# Generated deterministically by seda-macro-lef-normalizer-v1; recipe orfs-asap7-fakeram-m4-v1.
VERSION 5.8 ;
BUSBITCHARS "[]" ;
DIVIDERCHAR "/" ;

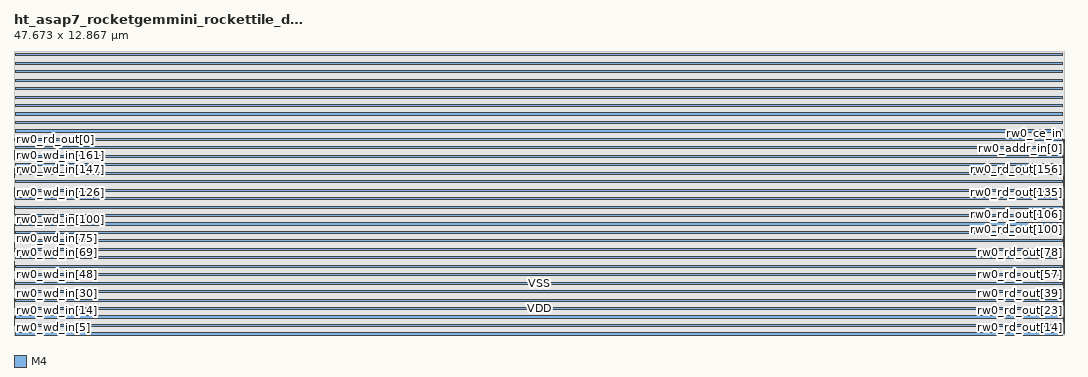
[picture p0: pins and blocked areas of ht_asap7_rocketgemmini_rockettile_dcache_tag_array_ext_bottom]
MACRO ht_asap7_rocketgemmini_rockettile_dcache_tag_array_ext_bottom
  FOREIGN ht_asap7_rocketgemmini_rockettile_dcache_tag_array_ext_bottom 0 0 ;
  CLASS BLOCK ;
  ORIGIN 0 0 ;
  SIZE 47.673 BY 12.867 ;
  SYMMETRY X Y R90 ;
  PIN rw0_wmask_in[0]
    DIRECTION INPUT ;
    USE SIGNAL ;
    SHAPE ABUTMENT ;
    PORT
      LAYER M4 ;
      RECT 0 0.048 0.024 0.072 ;
    END
  END rw0_wmask_in[0]
  PIN rw0_wmask_in[1]
    DIRECTION INPUT ;
    USE SIGNAL ;
    SHAPE ABUTMENT ;
    PORT
      LAYER M4 ;
      RECT 0 0.096 0.024 0.12 ;
    END
  END rw0_wmask_in[1]
  PIN rw0_wmask_in[2]
    DIRECTION INPUT ;
    USE SIGNAL ;
    SHAPE ABUTMENT ;
    PORT
      LAYER M4 ;
      RECT 0 0.144 0.024 0.168 ;
    END
  END rw0_wmask_in[2]
  PIN rw0_wmask_in[3]
    DIRECTION INPUT ;
    USE SIGNAL ;
    SHAPE ABUTMENT ;
    PORT
      LAYER M4 ;
      RECT 0 0.192 0.024 0.216 ;
    END
  END rw0_wmask_in[3]
  PIN rw0_wmask_in[4]
    DIRECTION INPUT ;
    USE SIGNAL ;
    SHAPE ABUTMENT ;
    PORT
      LAYER M4 ;
      RECT 0 0.24 0.024 0.264 ;
    END
  END rw0_wmask_in[4]
  PIN rw0_wmask_in[5]
    DIRECTION INPUT ;
    USE SIGNAL ;
    SHAPE ABUTMENT ;
    PORT
      LAYER M4 ;
      RECT 0 0.288 0.024 0.312 ;
    END
  END rw0_wmask_in[5]
  PIN rw0_wmask_in[6]
    DIRECTION INPUT ;
    USE SIGNAL ;
    SHAPE ABUTMENT ;
    PORT
      LAYER M4 ;
      RECT 0 0.336 0.024 0.36 ;
    END
  END rw0_wmask_in[6]
  PIN rw0_wmask_in[7]
    DIRECTION INPUT ;
    USE SIGNAL ;
    SHAPE ABUTMENT ;
    PORT
      LAYER M4 ;
      RECT 0 0.384 0.024 0.408 ;
    END
  END rw0_wmask_in[7]
  PIN rw0_wd_in[0]
    DIRECTION INPUT ;
    USE SIGNAL ;
    SHAPE ABUTMENT ;
    PORT
      LAYER M4 ;
      RECT 0 0.432 0.024 0.456 ;
    END
  END rw0_wd_in[0]
  PIN rw0_wd_in[1]
    DIRECTION INPUT ;
    USE SIGNAL ;
    SHAPE ABUTMENT ;
    PORT
      LAYER M4 ;
      RECT 0 0.48 0.024 0.504 ;
    END
  END rw0_wd_in[1]
  PIN rw0_wd_in[2]
    DIRECTION INPUT ;
    USE SIGNAL ;
    SHAPE ABUTMENT ;
    PORT
      LAYER M4 ;
      RECT 0 0.528 0.024 0.552 ;
    END
  END rw0_wd_in[2]
  PIN rw0_wd_in[3]
    DIRECTION INPUT ;
    USE SIGNAL ;
    SHAPE ABUTMENT ;
    PORT
      LAYER M4 ;
      RECT 0 0.576 0.024 0.6 ;
    END
  END rw0_wd_in[3]
  PIN rw0_wd_in[4]
    DIRECTION INPUT ;
    USE SIGNAL ;
    SHAPE ABUTMENT ;
    PORT
      LAYER M4 ;
      RECT 0 0.624 0.024 0.648 ;
    END
  END rw0_wd_in[4]
  PIN rw0_wd_in[5]
    DIRECTION INPUT ;
    USE SIGNAL ;
    SHAPE ABUTMENT ;
    PORT
      LAYER M4 ;
      RECT 0 0.672 0.024 0.696 ;
    END
  END rw0_wd_in[5]
  PIN rw0_wd_in[6]
    DIRECTION INPUT ;
    USE SIGNAL ;
    SHAPE ABUTMENT ;
    PORT
      LAYER M4 ;
      RECT 0 0.72 0.024 0.744 ;
    END
  END rw0_wd_in[6]
  PIN rw0_wd_in[7]
    DIRECTION INPUT ;
    USE SIGNAL ;
    SHAPE ABUTMENT ;
    PORT
      LAYER M4 ;
      RECT 0 0.768 0.024 0.792 ;
    END
  END rw0_wd_in[7]
  PIN rw0_wd_in[8]
    DIRECTION INPUT ;
    USE SIGNAL ;
    SHAPE ABUTMENT ;
    PORT
      LAYER M4 ;
      RECT 0 0.816 0.024 0.84 ;
    END
  END rw0_wd_in[8]
  PIN rw0_wd_in[9]
    DIRECTION INPUT ;
    USE SIGNAL ;
    SHAPE ABUTMENT ;
    PORT
      LAYER M4 ;
      RECT 0 0.864 0.024 0.888 ;
    END
  END rw0_wd_in[9]
  PIN rw0_wd_in[10]
    DIRECTION INPUT ;
    USE SIGNAL ;
    SHAPE ABUTMENT ;
    PORT
      LAYER M4 ;
      RECT 0 0.912 0.024 0.936 ;
    END
  END rw0_wd_in[10]
  PIN rw0_wd_in[11]
    DIRECTION INPUT ;
    USE SIGNAL ;
    SHAPE ABUTMENT ;
    PORT
      LAYER M4 ;
      RECT 0 0.96 0.024 0.984 ;
    END
  END rw0_wd_in[11]
  PIN rw0_wd_in[12]
    DIRECTION INPUT ;
    USE SIGNAL ;
    SHAPE ABUTMENT ;
    PORT
      LAYER M4 ;
      RECT 0 1.008 0.024 1.032 ;
    END
  END rw0_wd_in[12]
  PIN rw0_wd_in[13]
    DIRECTION INPUT ;
    USE SIGNAL ;
    SHAPE ABUTMENT ;
    PORT
      LAYER M4 ;
      RECT 0 1.056 0.024 1.08 ;
    END
  END rw0_wd_in[13]
  PIN rw0_wd_in[14]
    DIRECTION INPUT ;
    USE SIGNAL ;
    SHAPE ABUTMENT ;
    PORT
      LAYER M4 ;
      RECT 0 1.104 0.024 1.128 ;
    END
  END rw0_wd_in[14]
  PIN rw0_wd_in[15]
    DIRECTION INPUT ;
    USE SIGNAL ;
    SHAPE ABUTMENT ;
    PORT
      LAYER M4 ;
      RECT 0 1.152 0.024 1.176 ;
    END
  END rw0_wd_in[15]
  PIN rw0_wd_in[16]
    DIRECTION INPUT ;
    USE SIGNAL ;
    SHAPE ABUTMENT ;
    PORT
      LAYER M4 ;
      RECT 0 1.2 0.024 1.224 ;
    END
  END rw0_wd_in[16]
  PIN rw0_wd_in[17]
    DIRECTION INPUT ;
    USE SIGNAL ;
    SHAPE ABUTMENT ;
    PORT
      LAYER M4 ;
      RECT 0 1.248 0.024 1.272 ;
    END
  END rw0_wd_in[17]
  PIN rw0_wd_in[18]
    DIRECTION INPUT ;
    USE SIGNAL ;
    SHAPE ABUTMENT ;
    PORT
      LAYER M4 ;
      RECT 0 1.296 0.024 1.32 ;
    END
  END rw0_wd_in[18]
  PIN rw0_wd_in[19]
    DIRECTION INPUT ;
    USE SIGNAL ;
    SHAPE ABUTMENT ;
    PORT
      LAYER M4 ;
      RECT 0 1.344 0.024 1.368 ;
    END
  END rw0_wd_in[19]
  PIN rw0_wd_in[20]
    DIRECTION INPUT ;
    USE SIGNAL ;
    SHAPE ABUTMENT ;
    PORT
      LAYER M4 ;
      RECT 0 1.392 0.024 1.416 ;
    END
  END rw0_wd_in[20]
  PIN rw0_wd_in[21]
    DIRECTION INPUT ;
    USE SIGNAL ;
    SHAPE ABUTMENT ;
    PORT
      LAYER M4 ;
      RECT 0 1.44 0.024 1.464 ;
    END
  END rw0_wd_in[21]
  PIN rw0_wd_in[22]
    DIRECTION INPUT ;
    USE SIGNAL ;
    SHAPE ABUTMENT ;
    PORT
      LAYER M4 ;
      RECT 0 1.488 0.024 1.512 ;
    END
  END rw0_wd_in[22]
  PIN rw0_wd_in[23]
    DIRECTION INPUT ;
    USE SIGNAL ;
    SHAPE ABUTMENT ;
    PORT
      LAYER M4 ;
      RECT 0 1.536 0.024 1.56 ;
    END
  END rw0_wd_in[23]
  PIN rw0_wd_in[24]
    DIRECTION INPUT ;
    USE SIGNAL ;
    SHAPE ABUTMENT ;
    PORT
      LAYER M4 ;
      RECT 0 1.584 0.024 1.608 ;
    END
  END rw0_wd_in[24]
  PIN rw0_wd_in[25]
    DIRECTION INPUT ;
    USE SIGNAL ;
    SHAPE ABUTMENT ;
    PORT
      LAYER M4 ;
      RECT 0 1.632 0.024 1.656 ;
    END
  END rw0_wd_in[25]
  PIN rw0_wd_in[26]
    DIRECTION INPUT ;
    USE SIGNAL ;
    SHAPE ABUTMENT ;
    PORT
      LAYER M4 ;
      RECT 0 1.68 0.024 1.704 ;
    END
  END rw0_wd_in[26]
  PIN rw0_wd_in[27]
    DIRECTION INPUT ;
    USE SIGNAL ;
    SHAPE ABUTMENT ;
    PORT
      LAYER M4 ;
      RECT 0 1.728 0.024 1.752 ;
    END
  END rw0_wd_in[27]
  PIN rw0_wd_in[28]
    DIRECTION INPUT ;
    USE SIGNAL ;
    SHAPE ABUTMENT ;
    PORT
      LAYER M4 ;
      RECT 0 1.776 0.024 1.8 ;
    END
  END rw0_wd_in[28]
  PIN rw0_wd_in[29]
    DIRECTION INPUT ;
    USE SIGNAL ;
    SHAPE ABUTMENT ;
    PORT
      LAYER M4 ;
      RECT 0 1.824 0.024 1.848 ;
    END
  END rw0_wd_in[29]
  PIN rw0_wd_in[30]
    DIRECTION INPUT ;
    USE SIGNAL ;
    SHAPE ABUTMENT ;
    PORT
      LAYER M4 ;
      RECT 0 1.872 0.024 1.896 ;
    END
  END rw0_wd_in[30]
  PIN rw0_wd_in[31]
    DIRECTION INPUT ;
    USE SIGNAL ;
    SHAPE ABUTMENT ;
    PORT
      LAYER M4 ;
      RECT 0 1.92 0.024 1.944 ;
    END
  END rw0_wd_in[31]
  PIN rw0_wd_in[32]
    DIRECTION INPUT ;
    USE SIGNAL ;
    SHAPE ABUTMENT ;
    PORT
      LAYER M4 ;
      RECT 0 1.968 0.024 1.992 ;
    END
  END rw0_wd_in[32]
  PIN rw0_wd_in[33]
    DIRECTION INPUT ;
    USE SIGNAL ;
    SHAPE ABUTMENT ;
    PORT
      LAYER M4 ;
      RECT 0 2.016 0.024 2.04 ;
    END
  END rw0_wd_in[33]
  PIN rw0_wd_in[34]
    DIRECTION INPUT ;
    USE SIGNAL ;
    SHAPE ABUTMENT ;
    PORT
      LAYER M4 ;
      RECT 0 2.064 0.024 2.088 ;
    END
  END rw0_wd_in[34]
  PIN rw0_wd_in[35]
    DIRECTION INPUT ;
    USE SIGNAL ;
    SHAPE ABUTMENT ;
    PORT
      LAYER M4 ;
      RECT 0 2.112 0.024 2.136 ;
    END
  END rw0_wd_in[35]
  PIN rw0_wd_in[36]
    DIRECTION INPUT ;
    USE SIGNAL ;
    SHAPE ABUTMENT ;
    PORT
      LAYER M4 ;
      RECT 0 2.16 0.024 2.184 ;
    END
  END rw0_wd_in[36]
  PIN rw0_wd_in[37]
    DIRECTION INPUT ;
    USE SIGNAL ;
    SHAPE ABUTMENT ;
    PORT
      LAYER M4 ;
      RECT 0 2.208 0.024 2.232 ;
    END
  END rw0_wd_in[37]
  PIN rw0_wd_in[38]
    DIRECTION INPUT ;
    USE SIGNAL ;
    SHAPE ABUTMENT ;
    PORT
      LAYER M4 ;
      RECT 0 2.256 0.024 2.28 ;
    END
  END rw0_wd_in[38]
  PIN rw0_wd_in[39]
    DIRECTION INPUT ;
    USE SIGNAL ;
    SHAPE ABUTMENT ;
    PORT
      LAYER M4 ;
      RECT 0 2.304 0.024 2.328 ;
    END
  END rw0_wd_in[39]
  PIN rw0_wd_in[40]
    DIRECTION INPUT ;
    USE SIGNAL ;
    SHAPE ABUTMENT ;
    PORT
      LAYER M4 ;
      RECT 0 2.352 0.024 2.376 ;
    END
  END rw0_wd_in[40]
  PIN rw0_wd_in[41]
    DIRECTION INPUT ;
    USE SIGNAL ;
    SHAPE ABUTMENT ;
    PORT
      LAYER M4 ;
      RECT 0 2.4 0.024 2.424 ;
    END
  END rw0_wd_in[41]
  PIN rw0_wd_in[42]
    DIRECTION INPUT ;
    USE SIGNAL ;
    SHAPE ABUTMENT ;
    PORT
      LAYER M4 ;
      RECT 0 2.448 0.024 2.472 ;
    END
  END rw0_wd_in[42]
  PIN rw0_wd_in[43]
    DIRECTION INPUT ;
    USE SIGNAL ;
    SHAPE ABUTMENT ;
    PORT
      LAYER M4 ;
      RECT 0 2.496 0.024 2.52 ;
    END
  END rw0_wd_in[43]
  PIN rw0_wd_in[44]
    DIRECTION INPUT ;
    USE SIGNAL ;
    SHAPE ABUTMENT ;
    PORT
      LAYER M4 ;
      RECT 0 2.544 0.024 2.568 ;
    END
  END rw0_wd_in[44]
  PIN rw0_wd_in[45]
    DIRECTION INPUT ;
    USE SIGNAL ;
    SHAPE ABUTMENT ;
    PORT
      LAYER M4 ;
      RECT 0 2.592 0.024 2.616 ;
    END
  END rw0_wd_in[45]
  PIN rw0_wd_in[46]
    DIRECTION INPUT ;
    USE SIGNAL ;
    SHAPE ABUTMENT ;
    PORT
      LAYER M4 ;
      RECT 0 2.64 0.024 2.664 ;
    END
  END rw0_wd_in[46]
  PIN rw0_wd_in[47]
    DIRECTION INPUT ;
    USE SIGNAL ;
    SHAPE ABUTMENT ;
    PORT
      LAYER M4 ;
      RECT 0 2.688 0.024 2.712 ;
    END
  END rw0_wd_in[47]
  PIN rw0_wd_in[48]
    DIRECTION INPUT ;
    USE SIGNAL ;
    SHAPE ABUTMENT ;
    PORT
      LAYER M4 ;
      RECT 0 2.736 0.024 2.76 ;
    END
  END rw0_wd_in[48]
  PIN rw0_wd_in[49]
    DIRECTION INPUT ;
    USE SIGNAL ;
    SHAPE ABUTMENT ;
    PORT
      LAYER M4 ;
      RECT 0 2.784 0.024 2.808 ;
    END
  END rw0_wd_in[49]
  PIN rw0_wd_in[50]
    DIRECTION INPUT ;
    USE SIGNAL ;
    SHAPE ABUTMENT ;
    PORT
      LAYER M4 ;
      RECT 0 2.832 0.024 2.856 ;
    END
  END rw0_wd_in[50]
  PIN rw0_wd_in[51]
    DIRECTION INPUT ;
    USE SIGNAL ;
    SHAPE ABUTMENT ;
    PORT
      LAYER M4 ;
      RECT 0 2.88 0.024 2.904 ;
    END
  END rw0_wd_in[51]
  PIN rw0_wd_in[52]
    DIRECTION INPUT ;
    USE SIGNAL ;
    SHAPE ABUTMENT ;
    PORT
      LAYER M4 ;
      RECT 0 2.928 0.024 2.952 ;
    END
  END rw0_wd_in[52]
  PIN rw0_wd_in[53]
    DIRECTION INPUT ;
    USE SIGNAL ;
    SHAPE ABUTMENT ;
    PORT
      LAYER M4 ;
      RECT 0 2.976 0.024 3 ;
    END
  END rw0_wd_in[53]
  PIN rw0_wd_in[54]
    DIRECTION INPUT ;
    USE SIGNAL ;
    SHAPE ABUTMENT ;
    PORT
      LAYER M4 ;
      RECT 0 3.024 0.024 3.048 ;
    END
  END rw0_wd_in[54]
  PIN rw0_wd_in[55]
    DIRECTION INPUT ;
    USE SIGNAL ;
    SHAPE ABUTMENT ;
    PORT
      LAYER M4 ;
      RECT 0 3.072 0.024 3.096 ;
    END
  END rw0_wd_in[55]
  PIN rw0_wd_in[56]
    DIRECTION INPUT ;
    USE SIGNAL ;
    SHAPE ABUTMENT ;
    PORT
      LAYER M4 ;
      RECT 0 3.12 0.024 3.144 ;
    END
  END rw0_wd_in[56]
  PIN rw0_wd_in[57]
    DIRECTION INPUT ;
    USE SIGNAL ;
    SHAPE ABUTMENT ;
    PORT
      LAYER M4 ;
      RECT 0 3.168 0.024 3.192 ;
    END
  END rw0_wd_in[57]
  PIN rw0_wd_in[58]
    DIRECTION INPUT ;
    USE SIGNAL ;
    SHAPE ABUTMENT ;
    PORT
      LAYER M4 ;
      RECT 0 3.216 0.024 3.24 ;
    END
  END rw0_wd_in[58]
  PIN rw0_wd_in[59]
    DIRECTION INPUT ;
    USE SIGNAL ;
    SHAPE ABUTMENT ;
    PORT
      LAYER M4 ;
      RECT 0 3.264 0.024 3.288 ;
    END
  END rw0_wd_in[59]
  PIN rw0_wd_in[60]
    DIRECTION INPUT ;
    USE SIGNAL ;
    SHAPE ABUTMENT ;
    PORT
      LAYER M4 ;
      RECT 0 3.312 0.024 3.336 ;
    END
  END rw0_wd_in[60]
  PIN rw0_wd_in[61]
    DIRECTION INPUT ;
    USE SIGNAL ;
    SHAPE ABUTMENT ;
    PORT
      LAYER M4 ;
      RECT 0 3.36 0.024 3.384 ;
    END
  END rw0_wd_in[61]
  PIN rw0_wd_in[62]
    DIRECTION INPUT ;
    USE SIGNAL ;
    SHAPE ABUTMENT ;
    PORT
      LAYER M4 ;
      RECT 0 3.408 0.024 3.432 ;
    END
  END rw0_wd_in[62]
  PIN rw0_wd_in[63]
    DIRECTION INPUT ;
    USE SIGNAL ;
    SHAPE ABUTMENT ;
    PORT
      LAYER M4 ;
      RECT 0 3.456 0.024 3.48 ;
    END
  END rw0_wd_in[63]
  PIN rw0_wd_in[64]
    DIRECTION INPUT ;
    USE SIGNAL ;
    SHAPE ABUTMENT ;
    PORT
      LAYER M4 ;
      RECT 0 3.504 0.024 3.528 ;
    END
  END rw0_wd_in[64]
  PIN rw0_wd_in[65]
    DIRECTION INPUT ;
    USE SIGNAL ;
    SHAPE ABUTMENT ;
    PORT
      LAYER M4 ;
      RECT 0 3.552 0.024 3.576 ;
    END
  END rw0_wd_in[65]
  PIN rw0_wd_in[66]
    DIRECTION INPUT ;
    USE SIGNAL ;
    SHAPE ABUTMENT ;
    PORT
      LAYER M4 ;
      RECT 0 3.6 0.024 3.624 ;
    END
  END rw0_wd_in[66]
  PIN rw0_wd_in[67]
    DIRECTION INPUT ;
    USE SIGNAL ;
    SHAPE ABUTMENT ;
    PORT
      LAYER M4 ;
      RECT 0 3.648 0.024 3.672 ;
    END
  END rw0_wd_in[67]
  PIN rw0_wd_in[68]
    DIRECTION INPUT ;
    USE SIGNAL ;
    SHAPE ABUTMENT ;
    PORT
      LAYER M4 ;
      RECT 0 3.696 0.024 3.72 ;
    END
  END rw0_wd_in[68]
  PIN rw0_wd_in[69]
    DIRECTION INPUT ;
    USE SIGNAL ;
    SHAPE ABUTMENT ;
    PORT
      LAYER M4 ;
      RECT 0 3.744 0.024 3.768 ;
    END
  END rw0_wd_in[69]
  PIN rw0_wd_in[70]
    DIRECTION INPUT ;
    USE SIGNAL ;
    SHAPE ABUTMENT ;
    PORT
      LAYER M4 ;
      RECT 0 3.792 0.024 3.816 ;
    END
  END rw0_wd_in[70]
  PIN rw0_wd_in[71]
    DIRECTION INPUT ;
    USE SIGNAL ;
    SHAPE ABUTMENT ;
    PORT
      LAYER M4 ;
      RECT 0 3.84 0.024 3.864 ;
    END
  END rw0_wd_in[71]
  PIN rw0_wd_in[72]
    DIRECTION INPUT ;
    USE SIGNAL ;
    SHAPE ABUTMENT ;
    PORT
      LAYER M4 ;
      RECT 0 3.888 0.024 3.912 ;
    END
  END rw0_wd_in[72]
  PIN rw0_wd_in[73]
    DIRECTION INPUT ;
    USE SIGNAL ;
    SHAPE ABUTMENT ;
    PORT
      LAYER M4 ;
      RECT 0 3.936 0.024 3.96 ;
    END
  END rw0_wd_in[73]
  PIN rw0_wd_in[74]
    DIRECTION INPUT ;
    USE SIGNAL ;
    SHAPE ABUTMENT ;
    PORT
      LAYER M4 ;
      RECT 0 3.984 0.024 4.008 ;
    END
  END rw0_wd_in[74]
  PIN rw0_wd_in[75]
    DIRECTION INPUT ;
    USE SIGNAL ;
    SHAPE ABUTMENT ;
    PORT
      LAYER M4 ;
      RECT 0 4.032 0.024 4.056 ;
    END
  END rw0_wd_in[75]
  PIN rw0_wd_in[76]
    DIRECTION INPUT ;
    USE SIGNAL ;
    SHAPE ABUTMENT ;
    PORT
      LAYER M4 ;
      RECT 0 4.08 0.024 4.104 ;
    END
  END rw0_wd_in[76]
  PIN rw0_wd_in[77]
    DIRECTION INPUT ;
    USE SIGNAL ;
    SHAPE ABUTMENT ;
    PORT
      LAYER M4 ;
      RECT 0 4.128 0.024 4.152 ;
    END
  END rw0_wd_in[77]
  PIN rw0_wd_in[78]
    DIRECTION INPUT ;
    USE SIGNAL ;
    SHAPE ABUTMENT ;
    PORT
      LAYER M4 ;
      RECT 0 4.176 0.024 4.2 ;
    END
  END rw0_wd_in[78]
  PIN rw0_wd_in[79]
    DIRECTION INPUT ;
    USE SIGNAL ;
    SHAPE ABUTMENT ;
    PORT
      LAYER M4 ;
      RECT 0 4.224 0.024 4.248 ;
    END
  END rw0_wd_in[79]
  PIN rw0_wd_in[80]
    DIRECTION INPUT ;
    USE SIGNAL ;
    SHAPE ABUTMENT ;
    PORT
      LAYER M4 ;
      RECT 0 4.272 0.024 4.296 ;
    END
  END rw0_wd_in[80]
  PIN rw0_wd_in[81]
    DIRECTION INPUT ;
    USE SIGNAL ;
    SHAPE ABUTMENT ;
    PORT
      LAYER M4 ;
      RECT 0 4.32 0.024 4.344 ;
    END
  END rw0_wd_in[81]
  PIN rw0_wd_in[82]
    DIRECTION INPUT ;
    USE SIGNAL ;
    SHAPE ABUTMENT ;
    PORT
      LAYER M4 ;
      RECT 0 4.368 0.024 4.392 ;
    END
  END rw0_wd_in[82]
  PIN rw0_wd_in[83]
    DIRECTION INPUT ;
    USE SIGNAL ;
    SHAPE ABUTMENT ;
    PORT
      LAYER M4 ;
      RECT 0 4.416 0.024 4.44 ;
    END
  END rw0_wd_in[83]
  PIN rw0_wd_in[84]
    DIRECTION INPUT ;
    USE SIGNAL ;
    SHAPE ABUTMENT ;
    PORT
      LAYER M4 ;
      RECT 0 4.464 0.024 4.488 ;
    END
  END rw0_wd_in[84]
  PIN rw0_wd_in[85]
    DIRECTION INPUT ;
    USE SIGNAL ;
    SHAPE ABUTMENT ;
    PORT
      LAYER M4 ;
      RECT 0 4.512 0.024 4.536 ;
    END
  END rw0_wd_in[85]
  PIN rw0_wd_in[86]
    DIRECTION INPUT ;
    USE SIGNAL ;
    SHAPE ABUTMENT ;
    PORT
      LAYER M4 ;
      RECT 0 4.56 0.024 4.584 ;
    END
  END rw0_wd_in[86]
  PIN rw0_wd_in[87]
    DIRECTION INPUT ;
    USE SIGNAL ;
    SHAPE ABUTMENT ;
    PORT
      LAYER M4 ;
      RECT 0 4.608 0.024 4.632 ;
    END
  END rw0_wd_in[87]
  PIN rw0_wd_in[88]
    DIRECTION INPUT ;
    USE SIGNAL ;
    SHAPE ABUTMENT ;
    PORT
      LAYER M4 ;
      RECT 0 4.656 0.024 4.68 ;
    END
  END rw0_wd_in[88]
  PIN rw0_wd_in[89]
    DIRECTION INPUT ;
    USE SIGNAL ;
    SHAPE ABUTMENT ;
    PORT
      LAYER M4 ;
      RECT 0 4.704 0.024 4.728 ;
    END
  END rw0_wd_in[89]
  PIN rw0_wd_in[90]
    DIRECTION INPUT ;
    USE SIGNAL ;
    SHAPE ABUTMENT ;
    PORT
      LAYER M4 ;
      RECT 0 4.752 0.024 4.776 ;
    END
  END rw0_wd_in[90]
  PIN rw0_wd_in[91]
    DIRECTION INPUT ;
    USE SIGNAL ;
    SHAPE ABUTMENT ;
    PORT
      LAYER M4 ;
      RECT 0 4.8 0.024 4.824 ;
    END
  END rw0_wd_in[91]
  PIN rw0_wd_in[92]
    DIRECTION INPUT ;
    USE SIGNAL ;
    SHAPE ABUTMENT ;
    PORT
      LAYER M4 ;
      RECT 0 4.848 0.024 4.872 ;
    END
  END rw0_wd_in[92]
  PIN rw0_wd_in[93]
    DIRECTION INPUT ;
    USE SIGNAL ;
    SHAPE ABUTMENT ;
    PORT
      LAYER M4 ;
      RECT 0 4.896 0.024 4.92 ;
    END
  END rw0_wd_in[93]
  PIN rw0_wd_in[94]
    DIRECTION INPUT ;
    USE SIGNAL ;
    SHAPE ABUTMENT ;
    PORT
      LAYER M4 ;
      RECT 0 4.944 0.024 4.968 ;
    END
  END rw0_wd_in[94]
  PIN rw0_wd_in[95]
    DIRECTION INPUT ;
    USE SIGNAL ;
    SHAPE ABUTMENT ;
    PORT
      LAYER M4 ;
      RECT 0 4.992 0.024 5.016 ;
    END
  END rw0_wd_in[95]
  PIN rw0_wd_in[96]
    DIRECTION INPUT ;
    USE SIGNAL ;
    SHAPE ABUTMENT ;
    PORT
      LAYER M4 ;
      RECT 0 5.04 0.024 5.064 ;
    END
  END rw0_wd_in[96]
  PIN rw0_wd_in[97]
    DIRECTION INPUT ;
    USE SIGNAL ;
    SHAPE ABUTMENT ;
    PORT
      LAYER M4 ;
      RECT 0 5.088 0.024 5.112 ;
    END
  END rw0_wd_in[97]
  PIN rw0_wd_in[98]
    DIRECTION INPUT ;
    USE SIGNAL ;
    SHAPE ABUTMENT ;
    PORT
      LAYER M4 ;
      RECT 0 5.136 0.024 5.16 ;
    END
  END rw0_wd_in[98]
  PIN rw0_wd_in[99]
    DIRECTION INPUT ;
    USE SIGNAL ;
    SHAPE ABUTMENT ;
    PORT
      LAYER M4 ;
      RECT 0 5.184 0.024 5.208 ;
    END
  END rw0_wd_in[99]
  PIN rw0_wd_in[100]
    DIRECTION INPUT ;
    USE SIGNAL ;
    SHAPE ABUTMENT ;
    PORT
      LAYER M4 ;
      RECT 0 5.232 0.024 5.256 ;
    END
  END rw0_wd_in[100]
  PIN rw0_wd_in[101]
    DIRECTION INPUT ;
    USE SIGNAL ;
    SHAPE ABUTMENT ;
    PORT
      LAYER M4 ;
      RECT 0 5.28 0.024 5.304 ;
    END
  END rw0_wd_in[101]
  PIN rw0_wd_in[102]
    DIRECTION INPUT ;
    USE SIGNAL ;
    SHAPE ABUTMENT ;
    PORT
      LAYER M4 ;
      RECT 0 5.328 0.024 5.352 ;
    END
  END rw0_wd_in[102]
  PIN rw0_wd_in[103]
    DIRECTION INPUT ;
    USE SIGNAL ;
    SHAPE ABUTMENT ;
    PORT
      LAYER M4 ;
      RECT 0 5.376 0.024 5.4 ;
    END
  END rw0_wd_in[103]
  PIN rw0_wd_in[104]
    DIRECTION INPUT ;
    USE SIGNAL ;
    SHAPE ABUTMENT ;
    PORT
      LAYER M4 ;
      RECT 0 5.424 0.024 5.448 ;
    END
  END rw0_wd_in[104]
  PIN rw0_wd_in[105]
    DIRECTION INPUT ;
    USE SIGNAL ;
    SHAPE ABUTMENT ;
    PORT
      LAYER M4 ;
      RECT 0 5.472 0.024 5.496 ;
    END
  END rw0_wd_in[105]
  PIN rw0_wd_in[106]
    DIRECTION INPUT ;
    USE SIGNAL ;
    SHAPE ABUTMENT ;
    PORT
      LAYER M4 ;
      RECT 0 5.52 0.024 5.544 ;
    END
  END rw0_wd_in[106]
  PIN rw0_wd_in[107]
    DIRECTION INPUT ;
    USE SIGNAL ;
    SHAPE ABUTMENT ;
    PORT
      LAYER M4 ;
      RECT 0 5.568 0.024 5.592 ;
    END
  END rw0_wd_in[107]
  PIN rw0_wd_in[108]
    DIRECTION INPUT ;
    USE SIGNAL ;
    SHAPE ABUTMENT ;
    PORT
      LAYER M4 ;
      RECT 0 5.616 0.024 5.64 ;
    END
  END rw0_wd_in[108]
  PIN rw0_wd_in[109]
    DIRECTION INPUT ;
    USE SIGNAL ;
    SHAPE ABUTMENT ;
    PORT
      LAYER M4 ;
      RECT 0 5.664 0.024 5.688 ;
    END
  END rw0_wd_in[109]
  PIN rw0_wd_in[110]
    DIRECTION INPUT ;
    USE SIGNAL ;
    SHAPE ABUTMENT ;
    PORT
      LAYER M4 ;
      RECT 0 5.712 0.024 5.736 ;
    END
  END rw0_wd_in[110]
  PIN rw0_wd_in[111]
    DIRECTION INPUT ;
    USE SIGNAL ;
    SHAPE ABUTMENT ;
    PORT
      LAYER M4 ;
      RECT 0 5.76 0.024 5.784 ;
    END
  END rw0_wd_in[111]
  PIN rw0_wd_in[112]
    DIRECTION INPUT ;
    USE SIGNAL ;
    SHAPE ABUTMENT ;
    PORT
      LAYER M4 ;
      RECT 0 5.808 0.024 5.832 ;
    END
  END rw0_wd_in[112]
  PIN rw0_wd_in[113]
    DIRECTION INPUT ;
    USE SIGNAL ;
    SHAPE ABUTMENT ;
    PORT
      LAYER M4 ;
      RECT 0 5.856 0.024 5.88 ;
    END
  END rw0_wd_in[113]
  PIN rw0_wd_in[114]
    DIRECTION INPUT ;
    USE SIGNAL ;
    SHAPE ABUTMENT ;
    PORT
      LAYER M4 ;
      RECT 0 5.904 0.024 5.928 ;
    END
  END rw0_wd_in[114]
  PIN rw0_wd_in[115]
    DIRECTION INPUT ;
    USE SIGNAL ;
    SHAPE ABUTMENT ;
    PORT
      LAYER M4 ;
      RECT 0 5.952 0.024 5.976 ;
    END
  END rw0_wd_in[115]
  PIN rw0_wd_in[116]
    DIRECTION INPUT ;
    USE SIGNAL ;
    SHAPE ABUTMENT ;
    PORT
      LAYER M4 ;
      RECT 0 6 0.024 6.024 ;
    END
  END rw0_wd_in[116]
  PIN rw0_wd_in[117]
    DIRECTION INPUT ;
    USE SIGNAL ;
    SHAPE ABUTMENT ;
    PORT
      LAYER M4 ;
      RECT 0 6.048 0.024 6.072 ;
    END
  END rw0_wd_in[117]
  PIN rw0_wd_in[118]
    DIRECTION INPUT ;
    USE SIGNAL ;
    SHAPE ABUTMENT ;
    PORT
      LAYER M4 ;
      RECT 0 6.096 0.024 6.12 ;
    END
  END rw0_wd_in[118]
  PIN rw0_wd_in[119]
    DIRECTION INPUT ;
    USE SIGNAL ;
    SHAPE ABUTMENT ;
    PORT
      LAYER M4 ;
      RECT 0 6.144 0.024 6.168 ;
    END
  END rw0_wd_in[119]
  PIN rw0_wd_in[120]
    DIRECTION INPUT ;
    USE SIGNAL ;
    SHAPE ABUTMENT ;
    PORT
      LAYER M4 ;
      RECT 0 6.192 0.024 6.216 ;
    END
  END rw0_wd_in[120]
  PIN rw0_wd_in[121]
    DIRECTION INPUT ;
    USE SIGNAL ;
    SHAPE ABUTMENT ;
    PORT
      LAYER M4 ;
      RECT 0 6.24 0.024 6.264 ;
    END
  END rw0_wd_in[121]
  PIN rw0_wd_in[122]
    DIRECTION INPUT ;
    USE SIGNAL ;
    SHAPE ABUTMENT ;
    PORT
      LAYER M4 ;
      RECT 0 6.288 0.024 6.312 ;
    END
  END rw0_wd_in[122]
  PIN rw0_wd_in[123]
    DIRECTION INPUT ;
    USE SIGNAL ;
    SHAPE ABUTMENT ;
    PORT
      LAYER M4 ;
      RECT 0 6.336 0.024 6.36 ;
    END
  END rw0_wd_in[123]
  PIN rw0_wd_in[124]
    DIRECTION INPUT ;
    USE SIGNAL ;
    SHAPE ABUTMENT ;
    PORT
      LAYER M4 ;
      RECT 0 6.384 0.024 6.408 ;
    END
  END rw0_wd_in[124]
  PIN rw0_wd_in[125]
    DIRECTION INPUT ;
    USE SIGNAL ;
    SHAPE ABUTMENT ;
    PORT
      LAYER M4 ;
      RECT 0 6.432 0.024 6.456 ;
    END
  END rw0_wd_in[125]
  PIN rw0_wd_in[126]
    DIRECTION INPUT ;
    USE SIGNAL ;
    SHAPE ABUTMENT ;
    PORT
      LAYER M4 ;
      RECT 0 6.48 0.024 6.504 ;
    END
  END rw0_wd_in[126]
  PIN rw0_wd_in[127]
    DIRECTION INPUT ;
    USE SIGNAL ;
    SHAPE ABUTMENT ;
    PORT
      LAYER M4 ;
      RECT 0 6.528 0.024 6.552 ;
    END
  END rw0_wd_in[127]
  PIN rw0_wd_in[128]
    DIRECTION INPUT ;
    USE SIGNAL ;
    SHAPE ABUTMENT ;
    PORT
      LAYER M4 ;
      RECT 0 6.576 0.024 6.6 ;
    END
  END rw0_wd_in[128]
  PIN rw0_wd_in[129]
    DIRECTION INPUT ;
    USE SIGNAL ;
    SHAPE ABUTMENT ;
    PORT
      LAYER M4 ;
      RECT 0 6.624 0.024 6.648 ;
    END
  END rw0_wd_in[129]
  PIN rw0_wd_in[130]
    DIRECTION INPUT ;
    USE SIGNAL ;
    SHAPE ABUTMENT ;
    PORT
      LAYER M4 ;
      RECT 0 6.672 0.024 6.696 ;
    END
  END rw0_wd_in[130]
  PIN rw0_wd_in[131]
    DIRECTION INPUT ;
    USE SIGNAL ;
    SHAPE ABUTMENT ;
    PORT
      LAYER M4 ;
      RECT 0 6.72 0.024 6.744 ;
    END
  END rw0_wd_in[131]
  PIN rw0_wd_in[132]
    DIRECTION INPUT ;
    USE SIGNAL ;
    SHAPE ABUTMENT ;
    PORT
      LAYER M4 ;
      RECT 0 6.768 0.024 6.792 ;
    END
  END rw0_wd_in[132]
  PIN rw0_wd_in[133]
    DIRECTION INPUT ;
    USE SIGNAL ;
    SHAPE ABUTMENT ;
    PORT
      LAYER M4 ;
      RECT 0 6.816 0.024 6.84 ;
    END
  END rw0_wd_in[133]
  PIN rw0_wd_in[134]
    DIRECTION INPUT ;
    USE SIGNAL ;
    SHAPE ABUTMENT ;
    PORT
      LAYER M4 ;
      RECT 0 6.864 0.024 6.888 ;
    END
  END rw0_wd_in[134]
  PIN rw0_wd_in[135]
    DIRECTION INPUT ;
    USE SIGNAL ;
    SHAPE ABUTMENT ;
    PORT
      LAYER M4 ;
      RECT 0 6.912 0.024 6.936 ;
    END
  END rw0_wd_in[135]
  PIN rw0_wd_in[136]
    DIRECTION INPUT ;
    USE SIGNAL ;
    SHAPE ABUTMENT ;
    PORT
      LAYER M4 ;
      RECT 0 6.96 0.024 6.984 ;
    END
  END rw0_wd_in[136]
  PIN rw0_wd_in[137]
    DIRECTION INPUT ;
    USE SIGNAL ;
    SHAPE ABUTMENT ;
    PORT
      LAYER M4 ;
      RECT 0 7.008 0.024 7.032 ;
    END
  END rw0_wd_in[137]
  PIN rw0_wd_in[138]
    DIRECTION INPUT ;
    USE SIGNAL ;
    SHAPE ABUTMENT ;
    PORT
      LAYER M4 ;
      RECT 0 7.056 0.024 7.08 ;
    END
  END rw0_wd_in[138]
  PIN rw0_wd_in[139]
    DIRECTION INPUT ;
    USE SIGNAL ;
    SHAPE ABUTMENT ;
    PORT
      LAYER M4 ;
      RECT 0 7.104 0.024 7.128 ;
    END
  END rw0_wd_in[139]
  PIN rw0_wd_in[140]
    DIRECTION INPUT ;
    USE SIGNAL ;
    SHAPE ABUTMENT ;
    PORT
      LAYER M4 ;
      RECT 0 7.152 0.024 7.176 ;
    END
  END rw0_wd_in[140]
  PIN rw0_wd_in[141]
    DIRECTION INPUT ;
    USE SIGNAL ;
    SHAPE ABUTMENT ;
    PORT
      LAYER M4 ;
      RECT 0 7.2 0.024 7.224 ;
    END
  END rw0_wd_in[141]
  PIN rw0_wd_in[142]
    DIRECTION INPUT ;
    USE SIGNAL ;
    SHAPE ABUTMENT ;
    PORT
      LAYER M4 ;
      RECT 0 7.248 0.024 7.272 ;
    END
  END rw0_wd_in[142]
  PIN rw0_wd_in[143]
    DIRECTION INPUT ;
    USE SIGNAL ;
    SHAPE ABUTMENT ;
    PORT
      LAYER M4 ;
      RECT 0 7.296 0.024 7.32 ;
    END
  END rw0_wd_in[143]
  PIN rw0_wd_in[144]
    DIRECTION INPUT ;
    USE SIGNAL ;
    SHAPE ABUTMENT ;
    PORT
      LAYER M4 ;
      RECT 0 7.344 0.024 7.368 ;
    END
  END rw0_wd_in[144]
  PIN rw0_wd_in[145]
    DIRECTION INPUT ;
    USE SIGNAL ;
    SHAPE ABUTMENT ;
    PORT
      LAYER M4 ;
      RECT 0 7.392 0.024 7.416 ;
    END
  END rw0_wd_in[145]
  PIN rw0_wd_in[146]
    DIRECTION INPUT ;
    USE SIGNAL ;
    SHAPE ABUTMENT ;
    PORT
      LAYER M4 ;
      RECT 0 7.44 0.024 7.464 ;
    END
  END rw0_wd_in[146]
  PIN rw0_wd_in[147]
    DIRECTION INPUT ;
    USE SIGNAL ;
    SHAPE ABUTMENT ;
    PORT
      LAYER M4 ;
      RECT 0 7.488 0.024 7.512 ;
    END
  END rw0_wd_in[147]
  PIN rw0_wd_in[148]
    DIRECTION INPUT ;
    USE SIGNAL ;
    SHAPE ABUTMENT ;
    PORT
      LAYER M4 ;
      RECT 0 7.536 0.024 7.56 ;
    END
  END rw0_wd_in[148]
  PIN rw0_wd_in[149]
    DIRECTION INPUT ;
    USE SIGNAL ;
    SHAPE ABUTMENT ;
    PORT
      LAYER M4 ;
      RECT 0 7.584 0.024 7.608 ;
    END
  END rw0_wd_in[149]
  PIN rw0_wd_in[150]
    DIRECTION INPUT ;
    USE SIGNAL ;
    SHAPE ABUTMENT ;
    PORT
      LAYER M4 ;
      RECT 0 7.632 0.024 7.656 ;
    END
  END rw0_wd_in[150]
  PIN rw0_wd_in[151]
    DIRECTION INPUT ;
    USE SIGNAL ;
    SHAPE ABUTMENT ;
    PORT
      LAYER M4 ;
      RECT 0 7.68 0.024 7.704 ;
    END
  END rw0_wd_in[151]
  PIN rw0_wd_in[152]
    DIRECTION INPUT ;
    USE SIGNAL ;
    SHAPE ABUTMENT ;
    PORT
      LAYER M4 ;
      RECT 0 7.728 0.024 7.752 ;
    END
  END rw0_wd_in[152]
  PIN rw0_wd_in[153]
    DIRECTION INPUT ;
    USE SIGNAL ;
    SHAPE ABUTMENT ;
    PORT
      LAYER M4 ;
      RECT 0 7.776 0.024 7.8 ;
    END
  END rw0_wd_in[153]
  PIN rw0_wd_in[154]
    DIRECTION INPUT ;
    USE SIGNAL ;
    SHAPE ABUTMENT ;
    PORT
      LAYER M4 ;
      RECT 0 7.824 0.024 7.848 ;
    END
  END rw0_wd_in[154]
  PIN rw0_wd_in[155]
    DIRECTION INPUT ;
    USE SIGNAL ;
    SHAPE ABUTMENT ;
    PORT
      LAYER M4 ;
      RECT 0 7.872 0.024 7.896 ;
    END
  END rw0_wd_in[155]
  PIN rw0_wd_in[156]
    DIRECTION INPUT ;
    USE SIGNAL ;
    SHAPE ABUTMENT ;
    PORT
      LAYER M4 ;
      RECT 0 7.92 0.024 7.944 ;
    END
  END rw0_wd_in[156]
  PIN rw0_wd_in[157]
    DIRECTION INPUT ;
    USE SIGNAL ;
    SHAPE ABUTMENT ;
    PORT
      LAYER M4 ;
      RECT 0 7.968 0.024 7.992 ;
    END
  END rw0_wd_in[157]
  PIN rw0_wd_in[158]
    DIRECTION INPUT ;
    USE SIGNAL ;
    SHAPE ABUTMENT ;
    PORT
      LAYER M4 ;
      RECT 0 8.016 0.024 8.04 ;
    END
  END rw0_wd_in[158]
  PIN rw0_wd_in[159]
    DIRECTION INPUT ;
    USE SIGNAL ;
    SHAPE ABUTMENT ;
    PORT
      LAYER M4 ;
      RECT 0 8.064 0.024 8.088 ;
    END
  END rw0_wd_in[159]
  PIN rw0_wd_in[160]
    DIRECTION INPUT ;
    USE SIGNAL ;
    SHAPE ABUTMENT ;
    PORT
      LAYER M4 ;
      RECT 0 8.112 0.024 8.136 ;
    END
  END rw0_wd_in[160]
  PIN rw0_wd_in[161]
    DIRECTION INPUT ;
    USE SIGNAL ;
    SHAPE ABUTMENT ;
    PORT
      LAYER M4 ;
      RECT 0 8.16 0.024 8.184 ;
    END
  END rw0_wd_in[161]
  PIN rw0_wd_in[162]
    DIRECTION INPUT ;
    USE SIGNAL ;
    SHAPE ABUTMENT ;
    PORT
      LAYER M4 ;
      RECT 0 8.208 0.024 8.232 ;
    END
  END rw0_wd_in[162]
  PIN rw0_wd_in[163]
    DIRECTION INPUT ;
    USE SIGNAL ;
    SHAPE ABUTMENT ;
    PORT
      LAYER M4 ;
      RECT 0 8.256 0.024 8.28 ;
    END
  END rw0_wd_in[163]
  PIN rw0_wd_in[164]
    DIRECTION INPUT ;
    USE SIGNAL ;
    SHAPE ABUTMENT ;
    PORT
      LAYER M4 ;
      RECT 0 8.304 0.024 8.328 ;
    END
  END rw0_wd_in[164]
  PIN rw0_wd_in[165]
    DIRECTION INPUT ;
    USE SIGNAL ;
    SHAPE ABUTMENT ;
    PORT
      LAYER M4 ;
      RECT 0 8.352 0.024 8.376 ;
    END
  END rw0_wd_in[165]
  PIN rw0_wd_in[166]
    DIRECTION INPUT ;
    USE SIGNAL ;
    SHAPE ABUTMENT ;
    PORT
      LAYER M4 ;
      RECT 0 8.4 0.024 8.424 ;
    END
  END rw0_wd_in[166]
  PIN rw0_wd_in[167]
    DIRECTION INPUT ;
    USE SIGNAL ;
    SHAPE ABUTMENT ;
    PORT
      LAYER M4 ;
      RECT 0 8.448 0.024 8.472 ;
    END
  END rw0_wd_in[167]
  PIN rw0_wd_in[168]
    DIRECTION INPUT ;
    USE SIGNAL ;
    SHAPE ABUTMENT ;
    PORT
      LAYER M4 ;
      RECT 0 8.496 0.024 8.52 ;
    END
  END rw0_wd_in[168]
  PIN rw0_wd_in[169]
    DIRECTION INPUT ;
    USE SIGNAL ;
    SHAPE ABUTMENT ;
    PORT
      LAYER M4 ;
      RECT 0 8.544 0.024 8.568 ;
    END
  END rw0_wd_in[169]
  PIN rw0_wd_in[170]
    DIRECTION INPUT ;
    USE SIGNAL ;
    SHAPE ABUTMENT ;
    PORT
      LAYER M4 ;
      RECT 0 8.592 0.024 8.616 ;
    END
  END rw0_wd_in[170]
  PIN rw0_wd_in[171]
    DIRECTION INPUT ;
    USE SIGNAL ;
    SHAPE ABUTMENT ;
    PORT
      LAYER M4 ;
      RECT 0 8.64 0.024 8.664 ;
    END
  END rw0_wd_in[171]
  PIN rw0_wd_in[172]
    DIRECTION INPUT ;
    USE SIGNAL ;
    SHAPE ABUTMENT ;
    PORT
      LAYER M4 ;
      RECT 0 8.688 0.024 8.712 ;
    END
  END rw0_wd_in[172]
  PIN rw0_wd_in[173]
    DIRECTION INPUT ;
    USE SIGNAL ;
    SHAPE ABUTMENT ;
    PORT
      LAYER M4 ;
      RECT 0 8.736 0.024 8.76 ;
    END
  END rw0_wd_in[173]
  PIN rw0_wd_in[174]
    DIRECTION INPUT ;
    USE SIGNAL ;
    SHAPE ABUTMENT ;
    PORT
      LAYER M4 ;
      RECT 0 8.784 0.024 8.808 ;
    END
  END rw0_wd_in[174]
  PIN rw0_wd_in[175]
    DIRECTION INPUT ;
    USE SIGNAL ;
    SHAPE ABUTMENT ;
    PORT
      LAYER M4 ;
      RECT 0 8.832 0.024 8.856 ;
    END
  END rw0_wd_in[175]
  PIN rw0_rd_out[0]
    DIRECTION OUTPUT ;
    USE SIGNAL ;
    SHAPE ABUTMENT ;
    PORT
      LAYER M4 ;
      RECT 0 8.88 0.024 8.904 ;
    END
  END rw0_rd_out[0]
  PIN rw0_rd_out[1]
    DIRECTION OUTPUT ;
    USE SIGNAL ;
    SHAPE ABUTMENT ;
    PORT
      LAYER M4 ;
      RECT 47.649 0.048 47.673 0.072 ;
    END
  END rw0_rd_out[1]
  PIN rw0_rd_out[2]
    DIRECTION OUTPUT ;
    USE SIGNAL ;
    SHAPE ABUTMENT ;
    PORT
      LAYER M4 ;
      RECT 47.649 0.096 47.673 0.12 ;
    END
  END rw0_rd_out[2]
  PIN rw0_rd_out[3]
    DIRECTION OUTPUT ;
    USE SIGNAL ;
    SHAPE ABUTMENT ;
    PORT
      LAYER M4 ;
      RECT 47.649 0.144 47.673 0.168 ;
    END
  END rw0_rd_out[3]
  PIN rw0_rd_out[4]
    DIRECTION OUTPUT ;
    USE SIGNAL ;
    SHAPE ABUTMENT ;
    PORT
      LAYER M4 ;
      RECT 47.649 0.192 47.673 0.216 ;
    END
  END rw0_rd_out[4]
  PIN rw0_rd_out[5]
    DIRECTION OUTPUT ;
    USE SIGNAL ;
    SHAPE ABUTMENT ;
    PORT
      LAYER M4 ;
      RECT 47.649 0.24 47.673 0.264 ;
    END
  END rw0_rd_out[5]
  PIN rw0_rd_out[6]
    DIRECTION OUTPUT ;
    USE SIGNAL ;
    SHAPE ABUTMENT ;
    PORT
      LAYER M4 ;
      RECT 47.649 0.288 47.673 0.312 ;
    END
  END rw0_rd_out[6]
  PIN rw0_rd_out[7]
    DIRECTION OUTPUT ;
    USE SIGNAL ;
    SHAPE ABUTMENT ;
    PORT
      LAYER M4 ;
      RECT 47.649 0.336 47.673 0.36 ;
    END
  END rw0_rd_out[7]
  PIN rw0_rd_out[8]
    DIRECTION OUTPUT ;
    USE SIGNAL ;
    SHAPE ABUTMENT ;
    PORT
      LAYER M4 ;
      RECT 47.649 0.384 47.673 0.408 ;
    END
  END rw0_rd_out[8]
  PIN rw0_rd_out[9]
    DIRECTION OUTPUT ;
    USE SIGNAL ;
    SHAPE ABUTMENT ;
    PORT
      LAYER M4 ;
      RECT 47.649 0.432 47.673 0.456 ;
    END
  END rw0_rd_out[9]
  PIN rw0_rd_out[10]
    DIRECTION OUTPUT ;
    USE SIGNAL ;
    SHAPE ABUTMENT ;
    PORT
      LAYER M4 ;
      RECT 47.649 0.48 47.673 0.504 ;
    END
  END rw0_rd_out[10]
  PIN rw0_rd_out[11]
    DIRECTION OUTPUT ;
    USE SIGNAL ;
    SHAPE ABUTMENT ;
    PORT
      LAYER M4 ;
      RECT 47.649 0.528 47.673 0.552 ;
    END
  END rw0_rd_out[11]
  PIN rw0_rd_out[12]
    DIRECTION OUTPUT ;
    USE SIGNAL ;
    SHAPE ABUTMENT ;
    PORT
      LAYER M4 ;
      RECT 47.649 0.576 47.673 0.6 ;
    END
  END rw0_rd_out[12]
  PIN rw0_rd_out[13]
    DIRECTION OUTPUT ;
    USE SIGNAL ;
    SHAPE ABUTMENT ;
    PORT
      LAYER M4 ;
      RECT 47.649 0.624 47.673 0.648 ;
    END
  END rw0_rd_out[13]
  PIN rw0_rd_out[14]
    DIRECTION OUTPUT ;
    USE SIGNAL ;
    SHAPE ABUTMENT ;
    PORT
      LAYER M4 ;
      RECT 47.649 0.672 47.673 0.696 ;
    END
  END rw0_rd_out[14]
  PIN rw0_rd_out[15]
    DIRECTION OUTPUT ;
    USE SIGNAL ;
    SHAPE ABUTMENT ;
    PORT
      LAYER M4 ;
      RECT 47.649 0.72 47.673 0.744 ;
    END
  END rw0_rd_out[15]
  PIN rw0_rd_out[16]
    DIRECTION OUTPUT ;
    USE SIGNAL ;
    SHAPE ABUTMENT ;
    PORT
      LAYER M4 ;
      RECT 47.649 0.768 47.673 0.792 ;
    END
  END rw0_rd_out[16]
  PIN rw0_rd_out[17]
    DIRECTION OUTPUT ;
    USE SIGNAL ;
    SHAPE ABUTMENT ;
    PORT
      LAYER M4 ;
      RECT 47.649 0.816 47.673 0.84 ;
    END
  END rw0_rd_out[17]
  PIN rw0_rd_out[18]
    DIRECTION OUTPUT ;
    USE SIGNAL ;
    SHAPE ABUTMENT ;
    PORT
      LAYER M4 ;
      RECT 47.649 0.864 47.673 0.888 ;
    END
  END rw0_rd_out[18]
  PIN rw0_rd_out[19]
    DIRECTION OUTPUT ;
    USE SIGNAL ;
    SHAPE ABUTMENT ;
    PORT
      LAYER M4 ;
      RECT 47.649 0.912 47.673 0.936 ;
    END
  END rw0_rd_out[19]
  PIN rw0_rd_out[20]
    DIRECTION OUTPUT ;
    USE SIGNAL ;
    SHAPE ABUTMENT ;
    PORT
      LAYER M4 ;
      RECT 47.649 0.96 47.673 0.984 ;
    END
  END rw0_rd_out[20]
  PIN rw0_rd_out[21]
    DIRECTION OUTPUT ;
    USE SIGNAL ;
    SHAPE ABUTMENT ;
    PORT
      LAYER M4 ;
      RECT 47.649 1.008 47.673 1.032 ;
    END
  END rw0_rd_out[21]
  PIN rw0_rd_out[22]
    DIRECTION OUTPUT ;
    USE SIGNAL ;
    SHAPE ABUTMENT ;
    PORT
      LAYER M4 ;
      RECT 47.649 1.056 47.673 1.08 ;
    END
  END rw0_rd_out[22]
  PIN rw0_rd_out[23]
    DIRECTION OUTPUT ;
    USE SIGNAL ;
    SHAPE ABUTMENT ;
    PORT
      LAYER M4 ;
      RECT 47.649 1.104 47.673 1.128 ;
    END
  END rw0_rd_out[23]
  PIN rw0_rd_out[24]
    DIRECTION OUTPUT ;
    USE SIGNAL ;
    SHAPE ABUTMENT ;
    PORT
      LAYER M4 ;
      RECT 47.649 1.152 47.673 1.176 ;
    END
  END rw0_rd_out[24]
  PIN rw0_rd_out[25]
    DIRECTION OUTPUT ;
    USE SIGNAL ;
    SHAPE ABUTMENT ;
    PORT
      LAYER M4 ;
      RECT 47.649 1.2 47.673 1.224 ;
    END
  END rw0_rd_out[25]
  PIN rw0_rd_out[26]
    DIRECTION OUTPUT ;
    USE SIGNAL ;
    SHAPE ABUTMENT ;
    PORT
      LAYER M4 ;
      RECT 47.649 1.248 47.673 1.272 ;
    END
  END rw0_rd_out[26]
  PIN rw0_rd_out[27]
    DIRECTION OUTPUT ;
    USE SIGNAL ;
    SHAPE ABUTMENT ;
    PORT
      LAYER M4 ;
      RECT 47.649 1.296 47.673 1.32 ;
    END
  END rw0_rd_out[27]
  PIN rw0_rd_out[28]
    DIRECTION OUTPUT ;
    USE SIGNAL ;
    SHAPE ABUTMENT ;
    PORT
      LAYER M4 ;
      RECT 47.649 1.344 47.673 1.368 ;
    END
  END rw0_rd_out[28]
  PIN rw0_rd_out[29]
    DIRECTION OUTPUT ;
    USE SIGNAL ;
    SHAPE ABUTMENT ;
    PORT
      LAYER M4 ;
      RECT 47.649 1.392 47.673 1.416 ;
    END
  END rw0_rd_out[29]
  PIN rw0_rd_out[30]
    DIRECTION OUTPUT ;
    USE SIGNAL ;
    SHAPE ABUTMENT ;
    PORT
      LAYER M4 ;
      RECT 47.649 1.44 47.673 1.464 ;
    END
  END rw0_rd_out[30]
  PIN rw0_rd_out[31]
    DIRECTION OUTPUT ;
    USE SIGNAL ;
    SHAPE ABUTMENT ;
    PORT
      LAYER M4 ;
      RECT 47.649 1.488 47.673 1.512 ;
    END
  END rw0_rd_out[31]
  PIN rw0_rd_out[32]
    DIRECTION OUTPUT ;
    USE SIGNAL ;
    SHAPE ABUTMENT ;
    PORT
      LAYER M4 ;
      RECT 47.649 1.536 47.673 1.56 ;
    END
  END rw0_rd_out[32]
  PIN rw0_rd_out[33]
    DIRECTION OUTPUT ;
    USE SIGNAL ;
    SHAPE ABUTMENT ;
    PORT
      LAYER M4 ;
      RECT 47.649 1.584 47.673 1.608 ;
    END
  END rw0_rd_out[33]
  PIN rw0_rd_out[34]
    DIRECTION OUTPUT ;
    USE SIGNAL ;
    SHAPE ABUTMENT ;
    PORT
      LAYER M4 ;
      RECT 47.649 1.632 47.673 1.656 ;
    END
  END rw0_rd_out[34]
  PIN rw0_rd_out[35]
    DIRECTION OUTPUT ;
    USE SIGNAL ;
    SHAPE ABUTMENT ;
    PORT
      LAYER M4 ;
      RECT 47.649 1.68 47.673 1.704 ;
    END
  END rw0_rd_out[35]
  PIN rw0_rd_out[36]
    DIRECTION OUTPUT ;
    USE SIGNAL ;
    SHAPE ABUTMENT ;
    PORT
      LAYER M4 ;
      RECT 47.649 1.728 47.673 1.752 ;
    END
  END rw0_rd_out[36]
  PIN rw0_rd_out[37]
    DIRECTION OUTPUT ;
    USE SIGNAL ;
    SHAPE ABUTMENT ;
    PORT
      LAYER M4 ;
      RECT 47.649 1.776 47.673 1.8 ;
    END
  END rw0_rd_out[37]
  PIN rw0_rd_out[38]
    DIRECTION OUTPUT ;
    USE SIGNAL ;
    SHAPE ABUTMENT ;
    PORT
      LAYER M4 ;
      RECT 47.649 1.824 47.673 1.848 ;
    END
  END rw0_rd_out[38]
  PIN rw0_rd_out[39]
    DIRECTION OUTPUT ;
    USE SIGNAL ;
    SHAPE ABUTMENT ;
    PORT
      LAYER M4 ;
      RECT 47.649 1.872 47.673 1.896 ;
    END
  END rw0_rd_out[39]
  PIN rw0_rd_out[40]
    DIRECTION OUTPUT ;
    USE SIGNAL ;
    SHAPE ABUTMENT ;
    PORT
      LAYER M4 ;
      RECT 47.649 1.92 47.673 1.944 ;
    END
  END rw0_rd_out[40]
  PIN rw0_rd_out[41]
    DIRECTION OUTPUT ;
    USE SIGNAL ;
    SHAPE ABUTMENT ;
    PORT
      LAYER M4 ;
      RECT 47.649 1.968 47.673 1.992 ;
    END
  END rw0_rd_out[41]
  PIN rw0_rd_out[42]
    DIRECTION OUTPUT ;
    USE SIGNAL ;
    SHAPE ABUTMENT ;
    PORT
      LAYER M4 ;
      RECT 47.649 2.016 47.673 2.04 ;
    END
  END rw0_rd_out[42]
  PIN rw0_rd_out[43]
    DIRECTION OUTPUT ;
    USE SIGNAL ;
    SHAPE ABUTMENT ;
    PORT
      LAYER M4 ;
      RECT 47.649 2.064 47.673 2.088 ;
    END
  END rw0_rd_out[43]
  PIN rw0_rd_out[44]
    DIRECTION OUTPUT ;
    USE SIGNAL ;
    SHAPE ABUTMENT ;
    PORT
      LAYER M4 ;
      RECT 47.649 2.112 47.673 2.136 ;
    END
  END rw0_rd_out[44]
  PIN rw0_rd_out[45]
    DIRECTION OUTPUT ;
    USE SIGNAL ;
    SHAPE ABUTMENT ;
    PORT
      LAYER M4 ;
      RECT 47.649 2.16 47.673 2.184 ;
    END
  END rw0_rd_out[45]
  PIN rw0_rd_out[46]
    DIRECTION OUTPUT ;
    USE SIGNAL ;
    SHAPE ABUTMENT ;
    PORT
      LAYER M4 ;
      RECT 47.649 2.208 47.673 2.232 ;
    END
  END rw0_rd_out[46]
  PIN rw0_rd_out[47]
    DIRECTION OUTPUT ;
    USE SIGNAL ;
    SHAPE ABUTMENT ;
    PORT
      LAYER M4 ;
      RECT 47.649 2.256 47.673 2.28 ;
    END
  END rw0_rd_out[47]
  PIN rw0_rd_out[48]
    DIRECTION OUTPUT ;
    USE SIGNAL ;
    SHAPE ABUTMENT ;
    PORT
      LAYER M4 ;
      RECT 47.649 2.304 47.673 2.328 ;
    END
  END rw0_rd_out[48]
  PIN rw0_rd_out[49]
    DIRECTION OUTPUT ;
    USE SIGNAL ;
    SHAPE ABUTMENT ;
    PORT
      LAYER M4 ;
      RECT 47.649 2.352 47.673 2.376 ;
    END
  END rw0_rd_out[49]
  PIN rw0_rd_out[50]
    DIRECTION OUTPUT ;
    USE SIGNAL ;
    SHAPE ABUTMENT ;
    PORT
      LAYER M4 ;
      RECT 47.649 2.4 47.673 2.424 ;
    END
  END rw0_rd_out[50]
  PIN rw0_rd_out[51]
    DIRECTION OUTPUT ;
    USE SIGNAL ;
    SHAPE ABUTMENT ;
    PORT
      LAYER M4 ;
      RECT 47.649 2.448 47.673 2.472 ;
    END
  END rw0_rd_out[51]
  PIN rw0_rd_out[52]
    DIRECTION OUTPUT ;
    USE SIGNAL ;
    SHAPE ABUTMENT ;
    PORT
      LAYER M4 ;
      RECT 47.649 2.496 47.673 2.52 ;
    END
  END rw0_rd_out[52]
  PIN rw0_rd_out[53]
    DIRECTION OUTPUT ;
    USE SIGNAL ;
    SHAPE ABUTMENT ;
    PORT
      LAYER M4 ;
      RECT 47.649 2.544 47.673 2.568 ;
    END
  END rw0_rd_out[53]
  PIN rw0_rd_out[54]
    DIRECTION OUTPUT ;
    USE SIGNAL ;
    SHAPE ABUTMENT ;
    PORT
      LAYER M4 ;
      RECT 47.649 2.592 47.673 2.616 ;
    END
  END rw0_rd_out[54]
  PIN rw0_rd_out[55]
    DIRECTION OUTPUT ;
    USE SIGNAL ;
    SHAPE ABUTMENT ;
    PORT
      LAYER M4 ;
      RECT 47.649 2.64 47.673 2.664 ;
    END
  END rw0_rd_out[55]
  PIN rw0_rd_out[56]
    DIRECTION OUTPUT ;
    USE SIGNAL ;
    SHAPE ABUTMENT ;
    PORT
      LAYER M4 ;
      RECT 47.649 2.688 47.673 2.712 ;
    END
  END rw0_rd_out[56]
  PIN rw0_rd_out[57]
    DIRECTION OUTPUT ;
    USE SIGNAL ;
    SHAPE ABUTMENT ;
    PORT
      LAYER M4 ;
      RECT 47.649 2.736 47.673 2.76 ;
    END
  END rw0_rd_out[57]
  PIN rw0_rd_out[58]
    DIRECTION OUTPUT ;
    USE SIGNAL ;
    SHAPE ABUTMENT ;
    PORT
      LAYER M4 ;
      RECT 47.649 2.784 47.673 2.808 ;
    END
  END rw0_rd_out[58]
  PIN rw0_rd_out[59]
    DIRECTION OUTPUT ;
    USE SIGNAL ;
    SHAPE ABUTMENT ;
    PORT
      LAYER M4 ;
      RECT 47.649 2.832 47.673 2.856 ;
    END
  END rw0_rd_out[59]
  PIN rw0_rd_out[60]
    DIRECTION OUTPUT ;
    USE SIGNAL ;
    SHAPE ABUTMENT ;
    PORT
      LAYER M4 ;
      RECT 47.649 2.88 47.673 2.904 ;
    END
  END rw0_rd_out[60]
  PIN rw0_rd_out[61]
    DIRECTION OUTPUT ;
    USE SIGNAL ;
    SHAPE ABUTMENT ;
    PORT
      LAYER M4 ;
      RECT 47.649 2.928 47.673 2.952 ;
    END
  END rw0_rd_out[61]
  PIN rw0_rd_out[62]
    DIRECTION OUTPUT ;
    USE SIGNAL ;
    SHAPE ABUTMENT ;
    PORT
      LAYER M4 ;
      RECT 47.649 2.976 47.673 3 ;
    END
  END rw0_rd_out[62]
  PIN rw0_rd_out[63]
    DIRECTION OUTPUT ;
    USE SIGNAL ;
    SHAPE ABUTMENT ;
    PORT
      LAYER M4 ;
      RECT 47.649 3.024 47.673 3.048 ;
    END
  END rw0_rd_out[63]
  PIN rw0_rd_out[64]
    DIRECTION OUTPUT ;
    USE SIGNAL ;
    SHAPE ABUTMENT ;
    PORT
      LAYER M4 ;
      RECT 47.649 3.072 47.673 3.096 ;
    END
  END rw0_rd_out[64]
  PIN rw0_rd_out[65]
    DIRECTION OUTPUT ;
    USE SIGNAL ;
    SHAPE ABUTMENT ;
    PORT
      LAYER M4 ;
      RECT 47.649 3.12 47.673 3.144 ;
    END
  END rw0_rd_out[65]
  PIN rw0_rd_out[66]
    DIRECTION OUTPUT ;
    USE SIGNAL ;
    SHAPE ABUTMENT ;
    PORT
      LAYER M4 ;
      RECT 47.649 3.168 47.673 3.192 ;
    END
  END rw0_rd_out[66]
  PIN rw0_rd_out[67]
    DIRECTION OUTPUT ;
    USE SIGNAL ;
    SHAPE ABUTMENT ;
    PORT
      LAYER M4 ;
      RECT 47.649 3.216 47.673 3.24 ;
    END
  END rw0_rd_out[67]
  PIN rw0_rd_out[68]
    DIRECTION OUTPUT ;
    USE SIGNAL ;
    SHAPE ABUTMENT ;
    PORT
      LAYER M4 ;
      RECT 47.649 3.264 47.673 3.288 ;
    END
  END rw0_rd_out[68]
  PIN rw0_rd_out[69]
    DIRECTION OUTPUT ;
    USE SIGNAL ;
    SHAPE ABUTMENT ;
    PORT
      LAYER M4 ;
      RECT 47.649 3.312 47.673 3.336 ;
    END
  END rw0_rd_out[69]
  PIN rw0_rd_out[70]
    DIRECTION OUTPUT ;
    USE SIGNAL ;
    SHAPE ABUTMENT ;
    PORT
      LAYER M4 ;
      RECT 47.649 3.36 47.673 3.384 ;
    END
  END rw0_rd_out[70]
  PIN rw0_rd_out[71]
    DIRECTION OUTPUT ;
    USE SIGNAL ;
    SHAPE ABUTMENT ;
    PORT
      LAYER M4 ;
      RECT 47.649 3.408 47.673 3.432 ;
    END
  END rw0_rd_out[71]
  PIN rw0_rd_out[72]
    DIRECTION OUTPUT ;
    USE SIGNAL ;
    SHAPE ABUTMENT ;
    PORT
      LAYER M4 ;
      RECT 47.649 3.456 47.673 3.48 ;
    END
  END rw0_rd_out[72]
  PIN rw0_rd_out[73]
    DIRECTION OUTPUT ;
    USE SIGNAL ;
    SHAPE ABUTMENT ;
    PORT
      LAYER M4 ;
      RECT 47.649 3.504 47.673 3.528 ;
    END
  END rw0_rd_out[73]
  PIN rw0_rd_out[74]
    DIRECTION OUTPUT ;
    USE SIGNAL ;
    SHAPE ABUTMENT ;
    PORT
      LAYER M4 ;
      RECT 47.649 3.552 47.673 3.576 ;
    END
  END rw0_rd_out[74]
  PIN rw0_rd_out[75]
    DIRECTION OUTPUT ;
    USE SIGNAL ;
    SHAPE ABUTMENT ;
    PORT
      LAYER M4 ;
      RECT 47.649 3.6 47.673 3.624 ;
    END
  END rw0_rd_out[75]
  PIN rw0_rd_out[76]
    DIRECTION OUTPUT ;
    USE SIGNAL ;
    SHAPE ABUTMENT ;
    PORT
      LAYER M4 ;
      RECT 47.649 3.648 47.673 3.672 ;
    END
  END rw0_rd_out[76]
  PIN rw0_rd_out[77]
    DIRECTION OUTPUT ;
    USE SIGNAL ;
    SHAPE ABUTMENT ;
    PORT
      LAYER M4 ;
      RECT 47.649 3.696 47.673 3.72 ;
    END
  END rw0_rd_out[77]
  PIN rw0_rd_out[78]
    DIRECTION OUTPUT ;
    USE SIGNAL ;
    SHAPE ABUTMENT ;
    PORT
      LAYER M4 ;
      RECT 47.649 3.744 47.673 3.768 ;
    END
  END rw0_rd_out[78]
  PIN rw0_rd_out[79]
    DIRECTION OUTPUT ;
    USE SIGNAL ;
    SHAPE ABUTMENT ;
    PORT
      LAYER M4 ;
      RECT 47.649 3.792 47.673 3.816 ;
    END
  END rw0_rd_out[79]
  PIN rw0_rd_out[80]
    DIRECTION OUTPUT ;
    USE SIGNAL ;
    SHAPE ABUTMENT ;
    PORT
      LAYER M4 ;
      RECT 47.649 3.84 47.673 3.864 ;
    END
  END rw0_rd_out[80]
  PIN rw0_rd_out[81]
    DIRECTION OUTPUT ;
    USE SIGNAL ;
    SHAPE ABUTMENT ;
    PORT
      LAYER M4 ;
      RECT 47.649 3.888 47.673 3.912 ;
    END
  END rw0_rd_out[81]
  PIN rw0_rd_out[82]
    DIRECTION OUTPUT ;
    USE SIGNAL ;
    SHAPE ABUTMENT ;
    PORT
      LAYER M4 ;
      RECT 47.649 3.936 47.673 3.96 ;
    END
  END rw0_rd_out[82]
  PIN rw0_rd_out[83]
    DIRECTION OUTPUT ;
    USE SIGNAL ;
    SHAPE ABUTMENT ;
    PORT
      LAYER M4 ;
      RECT 47.649 3.984 47.673 4.008 ;
    END
  END rw0_rd_out[83]
  PIN rw0_rd_out[84]
    DIRECTION OUTPUT ;
    USE SIGNAL ;
    SHAPE ABUTMENT ;
    PORT
      LAYER M4 ;
      RECT 47.649 4.032 47.673 4.056 ;
    END
  END rw0_rd_out[84]
  PIN rw0_rd_out[85]
    DIRECTION OUTPUT ;
    USE SIGNAL ;
    SHAPE ABUTMENT ;
    PORT
      LAYER M4 ;
      RECT 47.649 4.08 47.673 4.104 ;
    END
  END rw0_rd_out[85]
  PIN rw0_rd_out[86]
    DIRECTION OUTPUT ;
    USE SIGNAL ;
    SHAPE ABUTMENT ;
    PORT
      LAYER M4 ;
      RECT 47.649 4.128 47.673 4.152 ;
    END
  END rw0_rd_out[86]
  PIN rw0_rd_out[87]
    DIRECTION OUTPUT ;
    USE SIGNAL ;
    SHAPE ABUTMENT ;
    PORT
      LAYER M4 ;
      RECT 47.649 4.176 47.673 4.2 ;
    END
  END rw0_rd_out[87]
  PIN rw0_rd_out[88]
    DIRECTION OUTPUT ;
    USE SIGNAL ;
    SHAPE ABUTMENT ;
    PORT
      LAYER M4 ;
      RECT 47.649 4.224 47.673 4.248 ;
    END
  END rw0_rd_out[88]
  PIN rw0_rd_out[89]
    DIRECTION OUTPUT ;
    USE SIGNAL ;
    SHAPE ABUTMENT ;
    PORT
      LAYER M4 ;
      RECT 47.649 4.272 47.673 4.296 ;
    END
  END rw0_rd_out[89]
  PIN rw0_rd_out[90]
    DIRECTION OUTPUT ;
    USE SIGNAL ;
    SHAPE ABUTMENT ;
    PORT
      LAYER M4 ;
      RECT 47.649 4.32 47.673 4.344 ;
    END
  END rw0_rd_out[90]
  PIN rw0_rd_out[91]
    DIRECTION OUTPUT ;
    USE SIGNAL ;
    SHAPE ABUTMENT ;
    PORT
      LAYER M4 ;
      RECT 47.649 4.368 47.673 4.392 ;
    END
  END rw0_rd_out[91]
  PIN rw0_rd_out[92]
    DIRECTION OUTPUT ;
    USE SIGNAL ;
    SHAPE ABUTMENT ;
    PORT
      LAYER M4 ;
      RECT 47.649 4.416 47.673 4.44 ;
    END
  END rw0_rd_out[92]
  PIN rw0_rd_out[93]
    DIRECTION OUTPUT ;
    USE SIGNAL ;
    SHAPE ABUTMENT ;
    PORT
      LAYER M4 ;
      RECT 47.649 4.464 47.673 4.488 ;
    END
  END rw0_rd_out[93]
  PIN rw0_rd_out[94]
    DIRECTION OUTPUT ;
    USE SIGNAL ;
    SHAPE ABUTMENT ;
    PORT
      LAYER M4 ;
      RECT 47.649 4.512 47.673 4.536 ;
    END
  END rw0_rd_out[94]
  PIN rw0_rd_out[95]
    DIRECTION OUTPUT ;
    USE SIGNAL ;
    SHAPE ABUTMENT ;
    PORT
      LAYER M4 ;
      RECT 47.649 4.56 47.673 4.584 ;
    END
  END rw0_rd_out[95]
  PIN rw0_rd_out[96]
    DIRECTION OUTPUT ;
    USE SIGNAL ;
    SHAPE ABUTMENT ;
    PORT
      LAYER M4 ;
      RECT 47.649 4.608 47.673 4.632 ;
    END
  END rw0_rd_out[96]
  PIN rw0_rd_out[97]
    DIRECTION OUTPUT ;
    USE SIGNAL ;
    SHAPE ABUTMENT ;
    PORT
      LAYER M4 ;
      RECT 47.649 4.656 47.673 4.68 ;
    END
  END rw0_rd_out[97]
  PIN rw0_rd_out[98]
    DIRECTION OUTPUT ;
    USE SIGNAL ;
    SHAPE ABUTMENT ;
    PORT
      LAYER M4 ;
      RECT 47.649 4.704 47.673 4.728 ;
    END
  END rw0_rd_out[98]
  PIN rw0_rd_out[99]
    DIRECTION OUTPUT ;
    USE SIGNAL ;
    SHAPE ABUTMENT ;
    PORT
      LAYER M4 ;
      RECT 47.649 4.752 47.673 4.776 ;
    END
  END rw0_rd_out[99]
  PIN rw0_rd_out[100]
    DIRECTION OUTPUT ;
    USE SIGNAL ;
    SHAPE ABUTMENT ;
    PORT
      LAYER M4 ;
      RECT 47.649 4.8 47.673 4.824 ;
    END
  END rw0_rd_out[100]
  PIN rw0_rd_out[101]
    DIRECTION OUTPUT ;
    USE SIGNAL ;
    SHAPE ABUTMENT ;
    PORT
      LAYER M4 ;
      RECT 47.649 4.848 47.673 4.872 ;
    END
  END rw0_rd_out[101]
  PIN rw0_rd_out[102]
    DIRECTION OUTPUT ;
    USE SIGNAL ;
    SHAPE ABUTMENT ;
    PORT
      LAYER M4 ;
      RECT 47.649 4.896 47.673 4.92 ;
    END
  END rw0_rd_out[102]
  PIN rw0_rd_out[103]
    DIRECTION OUTPUT ;
    USE SIGNAL ;
    SHAPE ABUTMENT ;
    PORT
      LAYER M4 ;
      RECT 47.649 4.944 47.673 4.968 ;
    END
  END rw0_rd_out[103]
  PIN rw0_rd_out[104]
    DIRECTION OUTPUT ;
    USE SIGNAL ;
    SHAPE ABUTMENT ;
    PORT
      LAYER M4 ;
      RECT 47.649 4.992 47.673 5.016 ;
    END
  END rw0_rd_out[104]
  PIN rw0_rd_out[105]
    DIRECTION OUTPUT ;
    USE SIGNAL ;
    SHAPE ABUTMENT ;
    PORT
      LAYER M4 ;
      RECT 47.649 5.04 47.673 5.064 ;
    END
  END rw0_rd_out[105]
  PIN rw0_rd_out[106]
    DIRECTION OUTPUT ;
    USE SIGNAL ;
    SHAPE ABUTMENT ;
    PORT
      LAYER M4 ;
      RECT 47.649 5.088 47.673 5.112 ;
    END
  END rw0_rd_out[106]
  PIN rw0_rd_out[107]
    DIRECTION OUTPUT ;
    USE SIGNAL ;
    SHAPE ABUTMENT ;
    PORT
      LAYER M4 ;
      RECT 47.649 5.136 47.673 5.16 ;
    END
  END rw0_rd_out[107]
  PIN rw0_rd_out[108]
    DIRECTION OUTPUT ;
    USE SIGNAL ;
    SHAPE ABUTMENT ;
    PORT
      LAYER M4 ;
      RECT 47.649 5.184 47.673 5.208 ;
    END
  END rw0_rd_out[108]
  PIN rw0_rd_out[109]
    DIRECTION OUTPUT ;
    USE SIGNAL ;
    SHAPE ABUTMENT ;
    PORT
      LAYER M4 ;
      RECT 47.649 5.232 47.673 5.256 ;
    END
  END rw0_rd_out[109]
  PIN rw0_rd_out[110]
    DIRECTION OUTPUT ;
    USE SIGNAL ;
    SHAPE ABUTMENT ;
    PORT
      LAYER M4 ;
      RECT 47.649 5.28 47.673 5.304 ;
    END
  END rw0_rd_out[110]
  PIN rw0_rd_out[111]
    DIRECTION OUTPUT ;
    USE SIGNAL ;
    SHAPE ABUTMENT ;
    PORT
      LAYER M4 ;
      RECT 47.649 5.328 47.673 5.352 ;
    END
  END rw0_rd_out[111]
  PIN rw0_rd_out[112]
    DIRECTION OUTPUT ;
    USE SIGNAL ;
    SHAPE ABUTMENT ;
    PORT
      LAYER M4 ;
      RECT 47.649 5.376 47.673 5.4 ;
    END
  END rw0_rd_out[112]
  PIN rw0_rd_out[113]
    DIRECTION OUTPUT ;
    USE SIGNAL ;
    SHAPE ABUTMENT ;
    PORT
      LAYER M4 ;
      RECT 47.649 5.424 47.673 5.448 ;
    END
  END rw0_rd_out[113]
  PIN rw0_rd_out[114]
    DIRECTION OUTPUT ;
    USE SIGNAL ;
    SHAPE ABUTMENT ;
    PORT
      LAYER M4 ;
      RECT 47.649 5.472 47.673 5.496 ;
    END
  END rw0_rd_out[114]
  PIN rw0_rd_out[115]
    DIRECTION OUTPUT ;
    USE SIGNAL ;
    SHAPE ABUTMENT ;
    PORT
      LAYER M4 ;
      RECT 47.649 5.52 47.673 5.544 ;
    END
  END rw0_rd_out[115]
  PIN rw0_rd_out[116]
    DIRECTION OUTPUT ;
    USE SIGNAL ;
    SHAPE ABUTMENT ;
    PORT
      LAYER M4 ;
      RECT 47.649 5.568 47.673 5.592 ;
    END
  END rw0_rd_out[116]
  PIN rw0_rd_out[117]
    DIRECTION OUTPUT ;
    USE SIGNAL ;
    SHAPE ABUTMENT ;
    PORT
      LAYER M4 ;
      RECT 47.649 5.616 47.673 5.64 ;
    END
  END rw0_rd_out[117]
  PIN rw0_rd_out[118]
    DIRECTION OUTPUT ;
    USE SIGNAL ;
    SHAPE ABUTMENT ;
    PORT
      LAYER M4 ;
      RECT 47.649 5.664 47.673 5.688 ;
    END
  END rw0_rd_out[118]
  PIN rw0_rd_out[119]
    DIRECTION OUTPUT ;
    USE SIGNAL ;
    SHAPE ABUTMENT ;
    PORT
      LAYER M4 ;
      RECT 47.649 5.712 47.673 5.736 ;
    END
  END rw0_rd_out[119]
  PIN rw0_rd_out[120]
    DIRECTION OUTPUT ;
    USE SIGNAL ;
    SHAPE ABUTMENT ;
    PORT
      LAYER M4 ;
      RECT 47.649 5.76 47.673 5.784 ;
    END
  END rw0_rd_out[120]
  PIN rw0_rd_out[121]
    DIRECTION OUTPUT ;
    USE SIGNAL ;
    SHAPE ABUTMENT ;
    PORT
      LAYER M4 ;
      RECT 47.649 5.808 47.673 5.832 ;
    END
  END rw0_rd_out[121]
  PIN rw0_rd_out[122]
    DIRECTION OUTPUT ;
    USE SIGNAL ;
    SHAPE ABUTMENT ;
    PORT
      LAYER M4 ;
      RECT 47.649 5.856 47.673 5.88 ;
    END
  END rw0_rd_out[122]
  PIN rw0_rd_out[123]
    DIRECTION OUTPUT ;
    USE SIGNAL ;
    SHAPE ABUTMENT ;
    PORT
      LAYER M4 ;
      RECT 47.649 5.904 47.673 5.928 ;
    END
  END rw0_rd_out[123]
  PIN rw0_rd_out[124]
    DIRECTION OUTPUT ;
    USE SIGNAL ;
    SHAPE ABUTMENT ;
    PORT
      LAYER M4 ;
      RECT 47.649 5.952 47.673 5.976 ;
    END
  END rw0_rd_out[124]
  PIN rw0_rd_out[125]
    DIRECTION OUTPUT ;
    USE SIGNAL ;
    SHAPE ABUTMENT ;
    PORT
      LAYER M4 ;
      RECT 47.649 6 47.673 6.024 ;
    END
  END rw0_rd_out[125]
  PIN rw0_rd_out[126]
    DIRECTION OUTPUT ;
    USE SIGNAL ;
    SHAPE ABUTMENT ;
    PORT
      LAYER M4 ;
      RECT 47.649 6.048 47.673 6.072 ;
    END
  END rw0_rd_out[126]
  PIN rw0_rd_out[127]
    DIRECTION OUTPUT ;
    USE SIGNAL ;
    SHAPE ABUTMENT ;
    PORT
      LAYER M4 ;
      RECT 47.649 6.096 47.673 6.12 ;
    END
  END rw0_rd_out[127]
  PIN rw0_rd_out[128]
    DIRECTION OUTPUT ;
    USE SIGNAL ;
    SHAPE ABUTMENT ;
    PORT
      LAYER M4 ;
      RECT 47.649 6.144 47.673 6.168 ;
    END
  END rw0_rd_out[128]
  PIN rw0_rd_out[129]
    DIRECTION OUTPUT ;
    USE SIGNAL ;
    SHAPE ABUTMENT ;
    PORT
      LAYER M4 ;
      RECT 47.649 6.192 47.673 6.216 ;
    END
  END rw0_rd_out[129]
  PIN rw0_rd_out[130]
    DIRECTION OUTPUT ;
    USE SIGNAL ;
    SHAPE ABUTMENT ;
    PORT
      LAYER M4 ;
      RECT 47.649 6.24 47.673 6.264 ;
    END
  END rw0_rd_out[130]
  PIN rw0_rd_out[131]
    DIRECTION OUTPUT ;
    USE SIGNAL ;
    SHAPE ABUTMENT ;
    PORT
      LAYER M4 ;
      RECT 47.649 6.288 47.673 6.312 ;
    END
  END rw0_rd_out[131]
  PIN rw0_rd_out[132]
    DIRECTION OUTPUT ;
    USE SIGNAL ;
    SHAPE ABUTMENT ;
    PORT
      LAYER M4 ;
      RECT 47.649 6.336 47.673 6.36 ;
    END
  END rw0_rd_out[132]
  PIN rw0_rd_out[133]
    DIRECTION OUTPUT ;
    USE SIGNAL ;
    SHAPE ABUTMENT ;
    PORT
      LAYER M4 ;
      RECT 47.649 6.384 47.673 6.408 ;
    END
  END rw0_rd_out[133]
  PIN rw0_rd_out[134]
    DIRECTION OUTPUT ;
    USE SIGNAL ;
    SHAPE ABUTMENT ;
    PORT
      LAYER M4 ;
      RECT 47.649 6.432 47.673 6.456 ;
    END
  END rw0_rd_out[134]
  PIN rw0_rd_out[135]
    DIRECTION OUTPUT ;
    USE SIGNAL ;
    SHAPE ABUTMENT ;
    PORT
      LAYER M4 ;
      RECT 47.649 6.48 47.673 6.504 ;
    END
  END rw0_rd_out[135]
  PIN rw0_rd_out[136]
    DIRECTION OUTPUT ;
    USE SIGNAL ;
    SHAPE ABUTMENT ;
    PORT
      LAYER M4 ;
      RECT 47.649 6.528 47.673 6.552 ;
    END
  END rw0_rd_out[136]
  PIN rw0_rd_out[137]
    DIRECTION OUTPUT ;
    USE SIGNAL ;
    SHAPE ABUTMENT ;
    PORT
      LAYER M4 ;
      RECT 47.649 6.576 47.673 6.6 ;
    END
  END rw0_rd_out[137]
  PIN rw0_rd_out[138]
    DIRECTION OUTPUT ;
    USE SIGNAL ;
    SHAPE ABUTMENT ;
    PORT
      LAYER M4 ;
      RECT 47.649 6.624 47.673 6.648 ;
    END
  END rw0_rd_out[138]
  PIN rw0_rd_out[139]
    DIRECTION OUTPUT ;
    USE SIGNAL ;
    SHAPE ABUTMENT ;
    PORT
      LAYER M4 ;
      RECT 47.649 6.672 47.673 6.696 ;
    END
  END rw0_rd_out[139]
  PIN rw0_rd_out[140]
    DIRECTION OUTPUT ;
    USE SIGNAL ;
    SHAPE ABUTMENT ;
    PORT
      LAYER M4 ;
      RECT 47.649 6.72 47.673 6.744 ;
    END
  END rw0_rd_out[140]
  PIN rw0_rd_out[141]
    DIRECTION OUTPUT ;
    USE SIGNAL ;
    SHAPE ABUTMENT ;
    PORT
      LAYER M4 ;
      RECT 47.649 6.768 47.673 6.792 ;
    END
  END rw0_rd_out[141]
  PIN rw0_rd_out[142]
    DIRECTION OUTPUT ;
    USE SIGNAL ;
    SHAPE ABUTMENT ;
    PORT
      LAYER M4 ;
      RECT 47.649 6.816 47.673 6.84 ;
    END
  END rw0_rd_out[142]
  PIN rw0_rd_out[143]
    DIRECTION OUTPUT ;
    USE SIGNAL ;
    SHAPE ABUTMENT ;
    PORT
      LAYER M4 ;
      RECT 47.649 6.864 47.673 6.888 ;
    END
  END rw0_rd_out[143]
  PIN rw0_rd_out[144]
    DIRECTION OUTPUT ;
    USE SIGNAL ;
    SHAPE ABUTMENT ;
    PORT
      LAYER M4 ;
      RECT 47.649 6.912 47.673 6.936 ;
    END
  END rw0_rd_out[144]
  PIN rw0_rd_out[145]
    DIRECTION OUTPUT ;
    USE SIGNAL ;
    SHAPE ABUTMENT ;
    PORT
      LAYER M4 ;
      RECT 47.649 6.96 47.673 6.984 ;
    END
  END rw0_rd_out[145]
  PIN rw0_rd_out[146]
    DIRECTION OUTPUT ;
    USE SIGNAL ;
    SHAPE ABUTMENT ;
    PORT
      LAYER M4 ;
      RECT 47.649 7.008 47.673 7.032 ;
    END
  END rw0_rd_out[146]
  PIN rw0_rd_out[147]
    DIRECTION OUTPUT ;
    USE SIGNAL ;
    SHAPE ABUTMENT ;
    PORT
      LAYER M4 ;
      RECT 47.649 7.056 47.673 7.08 ;
    END
  END rw0_rd_out[147]
  PIN rw0_rd_out[148]
    DIRECTION OUTPUT ;
    USE SIGNAL ;
    SHAPE ABUTMENT ;
    PORT
      LAYER M4 ;
      RECT 47.649 7.104 47.673 7.128 ;
    END
  END rw0_rd_out[148]
  PIN rw0_rd_out[149]
    DIRECTION OUTPUT ;
    USE SIGNAL ;
    SHAPE ABUTMENT ;
    PORT
      LAYER M4 ;
      RECT 47.649 7.152 47.673 7.176 ;
    END
  END rw0_rd_out[149]
  PIN rw0_rd_out[150]
    DIRECTION OUTPUT ;
    USE SIGNAL ;
    SHAPE ABUTMENT ;
    PORT
      LAYER M4 ;
      RECT 47.649 7.2 47.673 7.224 ;
    END
  END rw0_rd_out[150]
  PIN rw0_rd_out[151]
    DIRECTION OUTPUT ;
    USE SIGNAL ;
    SHAPE ABUTMENT ;
    PORT
      LAYER M4 ;
      RECT 47.649 7.248 47.673 7.272 ;
    END
  END rw0_rd_out[151]
  PIN rw0_rd_out[152]
    DIRECTION OUTPUT ;
    USE SIGNAL ;
    SHAPE ABUTMENT ;
    PORT
      LAYER M4 ;
      RECT 47.649 7.296 47.673 7.32 ;
    END
  END rw0_rd_out[152]
  PIN rw0_rd_out[153]
    DIRECTION OUTPUT ;
    USE SIGNAL ;
    SHAPE ABUTMENT ;
    PORT
      LAYER M4 ;
      RECT 47.649 7.344 47.673 7.368 ;
    END
  END rw0_rd_out[153]
  PIN rw0_rd_out[154]
    DIRECTION OUTPUT ;
    USE SIGNAL ;
    SHAPE ABUTMENT ;
    PORT
      LAYER M4 ;
      RECT 47.649 7.392 47.673 7.416 ;
    END
  END rw0_rd_out[154]
  PIN rw0_rd_out[155]
    DIRECTION OUTPUT ;
    USE SIGNAL ;
    SHAPE ABUTMENT ;
    PORT
      LAYER M4 ;
      RECT 47.649 7.44 47.673 7.464 ;
    END
  END rw0_rd_out[155]
  PIN rw0_rd_out[156]
    DIRECTION OUTPUT ;
    USE SIGNAL ;
    SHAPE ABUTMENT ;
    PORT
      LAYER M4 ;
      RECT 47.649 7.488 47.673 7.512 ;
    END
  END rw0_rd_out[156]
  PIN rw0_rd_out[157]
    DIRECTION OUTPUT ;
    USE SIGNAL ;
    SHAPE ABUTMENT ;
    PORT
      LAYER M4 ;
      RECT 47.649 7.536 47.673 7.56 ;
    END
  END rw0_rd_out[157]
  PIN rw0_rd_out[158]
    DIRECTION OUTPUT ;
    USE SIGNAL ;
    SHAPE ABUTMENT ;
    PORT
      LAYER M4 ;
      RECT 47.649 7.584 47.673 7.608 ;
    END
  END rw0_rd_out[158]
  PIN rw0_rd_out[159]
    DIRECTION OUTPUT ;
    USE SIGNAL ;
    SHAPE ABUTMENT ;
    PORT
      LAYER M4 ;
      RECT 47.649 7.632 47.673 7.656 ;
    END
  END rw0_rd_out[159]
  PIN rw0_rd_out[160]
    DIRECTION OUTPUT ;
    USE SIGNAL ;
    SHAPE ABUTMENT ;
    PORT
      LAYER M4 ;
      RECT 47.649 7.68 47.673 7.704 ;
    END
  END rw0_rd_out[160]
  PIN rw0_rd_out[161]
    DIRECTION OUTPUT ;
    USE SIGNAL ;
    SHAPE ABUTMENT ;
    PORT
      LAYER M4 ;
      RECT 47.649 7.728 47.673 7.752 ;
    END
  END rw0_rd_out[161]
  PIN rw0_rd_out[162]
    DIRECTION OUTPUT ;
    USE SIGNAL ;
    SHAPE ABUTMENT ;
    PORT
      LAYER M4 ;
      RECT 47.649 7.776 47.673 7.8 ;
    END
  END rw0_rd_out[162]
  PIN rw0_rd_out[163]
    DIRECTION OUTPUT ;
    USE SIGNAL ;
    SHAPE ABUTMENT ;
    PORT
      LAYER M4 ;
      RECT 47.649 7.824 47.673 7.848 ;
    END
  END rw0_rd_out[163]
  PIN rw0_rd_out[164]
    DIRECTION OUTPUT ;
    USE SIGNAL ;
    SHAPE ABUTMENT ;
    PORT
      LAYER M4 ;
      RECT 47.649 7.872 47.673 7.896 ;
    END
  END rw0_rd_out[164]
  PIN rw0_rd_out[165]
    DIRECTION OUTPUT ;
    USE SIGNAL ;
    SHAPE ABUTMENT ;
    PORT
      LAYER M4 ;
      RECT 47.649 7.92 47.673 7.944 ;
    END
  END rw0_rd_out[165]
  PIN rw0_rd_out[166]
    DIRECTION OUTPUT ;
    USE SIGNAL ;
    SHAPE ABUTMENT ;
    PORT
      LAYER M4 ;
      RECT 47.649 7.968 47.673 7.992 ;
    END
  END rw0_rd_out[166]
  PIN rw0_rd_out[167]
    DIRECTION OUTPUT ;
    USE SIGNAL ;
    SHAPE ABUTMENT ;
    PORT
      LAYER M4 ;
      RECT 47.649 8.016 47.673 8.04 ;
    END
  END rw0_rd_out[167]
  PIN rw0_rd_out[168]
    DIRECTION OUTPUT ;
    USE SIGNAL ;
    SHAPE ABUTMENT ;
    PORT
      LAYER M4 ;
      RECT 47.649 8.064 47.673 8.088 ;
    END
  END rw0_rd_out[168]
  PIN rw0_rd_out[169]
    DIRECTION OUTPUT ;
    USE SIGNAL ;
    SHAPE ABUTMENT ;
    PORT
      LAYER M4 ;
      RECT 47.649 8.112 47.673 8.136 ;
    END
  END rw0_rd_out[169]
  PIN rw0_rd_out[170]
    DIRECTION OUTPUT ;
    USE SIGNAL ;
    SHAPE ABUTMENT ;
    PORT
      LAYER M4 ;
      RECT 47.649 8.16 47.673 8.184 ;
    END
  END rw0_rd_out[170]
  PIN rw0_rd_out[171]
    DIRECTION OUTPUT ;
    USE SIGNAL ;
    SHAPE ABUTMENT ;
    PORT
      LAYER M4 ;
      RECT 47.649 8.208 47.673 8.232 ;
    END
  END rw0_rd_out[171]
  PIN rw0_rd_out[172]
    DIRECTION OUTPUT ;
    USE SIGNAL ;
    SHAPE ABUTMENT ;
    PORT
      LAYER M4 ;
      RECT 47.649 8.256 47.673 8.28 ;
    END
  END rw0_rd_out[172]
  PIN rw0_rd_out[173]
    DIRECTION OUTPUT ;
    USE SIGNAL ;
    SHAPE ABUTMENT ;
    PORT
      LAYER M4 ;
      RECT 47.649 8.304 47.673 8.328 ;
    END
  END rw0_rd_out[173]
  PIN rw0_rd_out[174]
    DIRECTION OUTPUT ;
    USE SIGNAL ;
    SHAPE ABUTMENT ;
    PORT
      LAYER M4 ;
      RECT 47.649 8.352 47.673 8.376 ;
    END
  END rw0_rd_out[174]
  PIN rw0_rd_out[175]
    DIRECTION OUTPUT ;
    USE SIGNAL ;
    SHAPE ABUTMENT ;
    PORT
      LAYER M4 ;
      RECT 47.649 8.4 47.673 8.424 ;
    END
  END rw0_rd_out[175]
  PIN rw0_addr_in[0]
    DIRECTION INPUT ;
    USE SIGNAL ;
    SHAPE ABUTMENT ;
    PORT
      LAYER M4 ;
      RECT 47.649 8.448 47.673 8.472 ;
    END
  END rw0_addr_in[0]
  PIN rw0_addr_in[1]
    DIRECTION INPUT ;
    USE SIGNAL ;
    SHAPE ABUTMENT ;
    PORT
      LAYER M4 ;
      RECT 47.649 8.496 47.673 8.52 ;
    END
  END rw0_addr_in[1]
  PIN rw0_addr_in[2]
    DIRECTION INPUT ;
    USE SIGNAL ;
    SHAPE ABUTMENT ;
    PORT
      LAYER M4 ;
      RECT 47.649 8.544 47.673 8.568 ;
    END
  END rw0_addr_in[2]
  PIN rw0_addr_in[3]
    DIRECTION INPUT ;
    USE SIGNAL ;
    SHAPE ABUTMENT ;
    PORT
      LAYER M4 ;
      RECT 47.649 8.592 47.673 8.616 ;
    END
  END rw0_addr_in[3]
  PIN rw0_addr_in[4]
    DIRECTION INPUT ;
    USE SIGNAL ;
    SHAPE ABUTMENT ;
    PORT
      LAYER M4 ;
      RECT 47.649 8.64 47.673 8.664 ;
    END
  END rw0_addr_in[4]
  PIN rw0_addr_in[5]
    DIRECTION INPUT ;
    USE SIGNAL ;
    SHAPE ABUTMENT ;
    PORT
      LAYER M4 ;
      RECT 47.649 8.688 47.673 8.712 ;
    END
  END rw0_addr_in[5]
  PIN rw0_we_in
    DIRECTION INPUT ;
    USE SIGNAL ;
    SHAPE ABUTMENT ;
    PORT
      LAYER M4 ;
      RECT 47.649 8.736 47.673 8.76 ;
    END
  END rw0_we_in
  PIN rw0_ce_in
    DIRECTION INPUT ;
    USE SIGNAL ;
    SHAPE ABUTMENT ;
    PORT
      LAYER M4 ;
      RECT 47.649 8.784 47.673 8.808 ;
    END
  END rw0_ce_in
  PIN rw0_clk
    DIRECTION INPUT ;
    USE SIGNAL ;
    SHAPE ABUTMENT ;
    PORT
      LAYER M4 ;
      RECT 47.649 8.832 47.673 8.856 ;
    END
  END rw0_clk
  PIN VSS
    DIRECTION INOUT ;
    USE GROUND ;
    PORT
      LAYER M4 ;
      RECT 0.048 0 47.625 0.096 ;
      RECT 0.048 0.768 47.625 0.864 ;
      RECT 0.048 1.536 47.625 1.632 ;
      RECT 0.048 2.304 47.625 2.4 ;
      RECT 0.048 3.072 47.625 3.168 ;
      RECT 0.048 3.84 47.625 3.936 ;
      RECT 0.048 4.608 47.625 4.704 ;
      RECT 0.048 5.376 47.625 5.472 ;
      RECT 0.048 6.144 47.625 6.24 ;
      RECT 0.048 6.912 47.625 7.008 ;
      RECT 0.048 7.68 47.625 7.776 ;
      RECT 0.048 8.448 47.625 8.544 ;
      RECT 0.048 9.216 47.625 9.312 ;
      RECT 0.048 9.984 47.625 10.08 ;
      RECT 0.048 10.752 47.625 10.848 ;
      RECT 0.048 11.52 47.625 11.616 ;
      RECT 0.048 12.288 47.625 12.384 ;
    END
  END VSS
  PIN VDD
    DIRECTION INOUT ;
    USE POWER ;
    PORT
      LAYER M4 ;
      RECT 0.048 0.384 47.625 0.48 ;
      RECT 0.048 1.152 47.625 1.248 ;
      RECT 0.048 1.92 47.625 2.016 ;
      RECT 0.048 2.688 47.625 2.784 ;
      RECT 0.048 3.456 47.625 3.552 ;
      RECT 0.048 4.224 47.625 4.32 ;
      RECT 0.048 4.992 47.625 5.088 ;
      RECT 0.048 5.76 47.625 5.856 ;
      RECT 0.048 6.528 47.625 6.624 ;
      RECT 0.048 7.296 47.625 7.392 ;
      RECT 0.048 8.064 47.625 8.16 ;
      RECT 0.048 8.832 47.625 8.928 ;
      RECT 0.048 9.6 47.625 9.696 ;
      RECT 0.048 10.368 47.625 10.464 ;
      RECT 0.048 11.136 47.625 11.232 ;
      RECT 0.048 11.904 47.625 12 ;
      RECT 0.048 12.672 47.625 12.768 ;
    END
  END VDD
  OBS
    LAYER M1 ;
    RECT 0 0 47.673 12.867 ;
    LAYER M2 ;
    RECT 0 0 47.673 12.867 ;
    LAYER M3 ;
    RECT 0 0 47.673 12.867 ;
  END
END ht_asap7_rocketgemmini_rockettile_dcache_tag_array_ext_bottom

END LIBRARY
